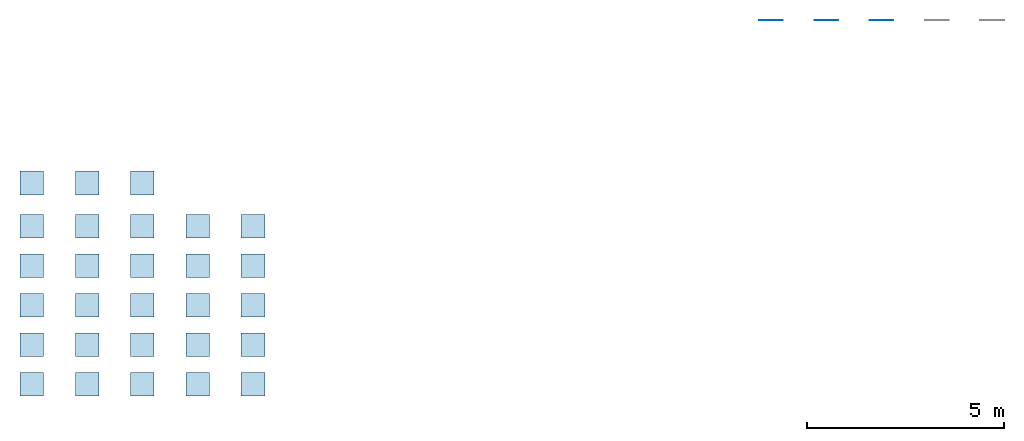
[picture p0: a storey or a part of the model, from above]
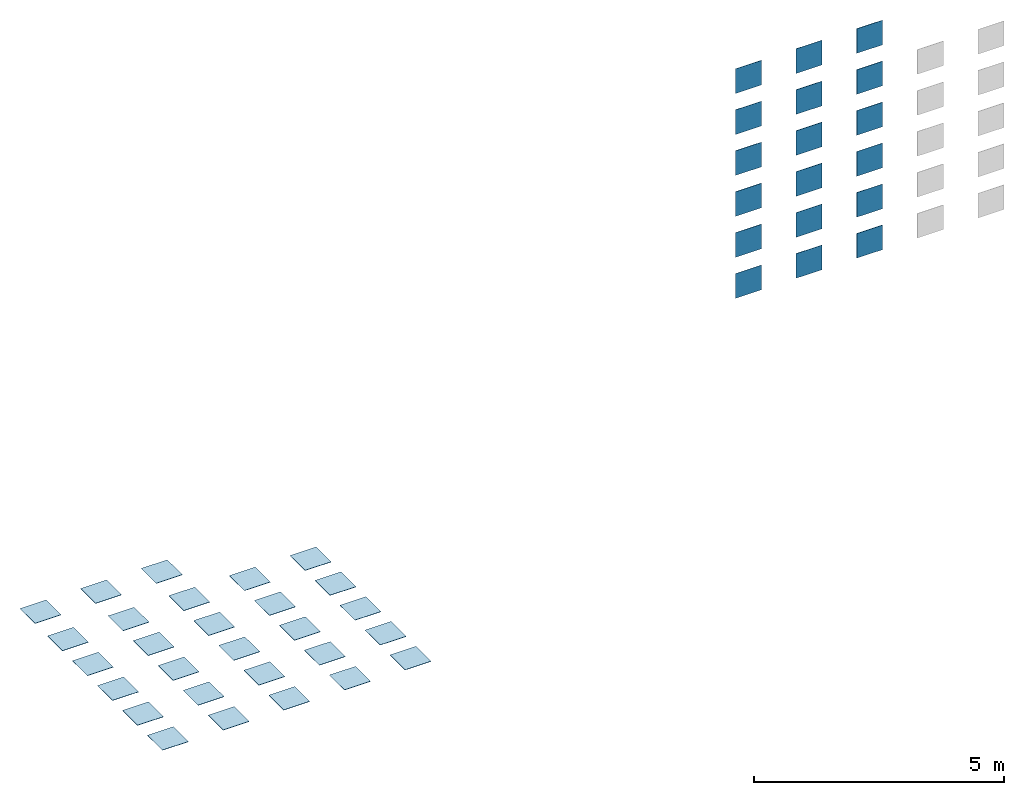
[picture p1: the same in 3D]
Properties of the parts of a building model (IFC2X3), part 1 of 2

# File
Description: ViewDefinition [CoordinationView]
File name: Número de proyecto
Time: 2017-10-18T16:32:32
Written by: The EXPRESS Data Manager Version 5.02.0100.07 : 28 Aug 2013
Made in: 20140606_1530(x64) - Exporter 2015.0.2014.0606 - Default UI
Comment: STEP Physical File produced by: The EXPRESS Data Manager Version 5.02.0100.07 : 28 Aug 2013 * Module: EDMstepFileFactory/EDMstandAlone * Creation date: Wed Oct 18 16:32:32 2017 * Host: REVIT * Database: C:\Users\corte\AppData\Local\Temp\{179764BC-A99F-427C-84EC-D29EAF626511}\ifc * Database version: 5507 * Database creation date: Wed Oct 18 16:32:31 2017 * Schema: IFC2X3 * Model: DataRepository.ifc * Model creation date: Wed Oct 18 16:32:31 2017 * Header model: DataRepository.ifc_HeaderModel * Header model creation date: Wed Oct 18 16:32:31 2017 * EDMuser: sdai-user * EDMgroup: sdai-group * License ID and type: 5605 : Permanent license. Expiry date: * EDMstepFileFactory options: 020000

# IfcProject, Número de proyecto
LongName: Nombre de proyecto; Phase: Estado de proyecto

# IfcSite, Default
RefLatitude: 40, 25, 0, 86975; RefLongitude: -3, -42, -1, -243858; RefElevation: 0 m
Otros - Categoría: Información de proyecto; Dirección de proyecto: Introduzca dirección aquí; Estado de proyecto: Estado de proyecto; Fecha de emisión de proyecto: Fecha de emisión; Nombre de cliente: Propietario; Nombre de proyecto: Nombre de proyecto; Número de proyecto: Número de proyecto

# IfcBuilding
Pset_BuildingCommon - NumberOfStoreys: 1
Otros - Categoría: Información de proyecto; Dirección de proyecto: Introduzca dirección aquí; Estado de proyecto: Estado de proyecto; Fecha de emisión de proyecto: Fecha de emisión; Nombre de cliente: Propietario; Nombre de proyecto: Nombre de proyecto; Número de proyecto: Número de proyecto

# IfcBuildingStorey, BENACO FLOOR TILES
LongName: BENACO FLOOR TILES; Elevation: 0 m
Restricciones - Altura base: Punto base del proyecto; Alzado: 0 m
Cotas - Altura de cálculo: 0 m
Datos de identidad - Estructura: no; Nombre: BENACO FLOOR TILES; Planta de edificio: yes; Nombre de tipo: Nivel 1
Otros - Categoría: Niveles; Familia: Nivel: Nivel 1; Familia y tipo: Nivel: Nivel 1; ID de tipo: Nivel: Nivel 1; Tipo: Nivel: Nivel 1; Nombre de familia: Nivel
Gráficos - Color: 0; Grosor de línea: 1; Patrón de línea: Trazo punto; Símbolo: Extremo de nivel: Extremo de nivel; Símbolo en extremo 1 por defecto: no; Símbolo en extremo 2 por defecto: yes

# IfcSlab: Suelo:VIVES BENACO BEIGE 20x20, Suelo:VIVES BENACO BEIGE 20x20:194564
In: BENACO FLOOR TILES
PredefinedType: FLOOR; Material: VIVES BENACO BEIGE 20x20 0.008 m
Pset_SlabCommon - IsExternal: no; LoadBearing: yes; PitchAngle: 0 deg; Reference: VIVES BENACO BEIGE 20x20; ThermalTransmittance: 187.5 kg/K/s3
Pset_ManufacturerTypeInformation - Manufacturer: VIVES Azulejos y Gres S.A.
Cotas - Área: 0.36 m2; Grosor: 0.008 m; Perímetro: 2.4 m; Volumen: 0.00288 m3
Estructura - Activar modelo analítico: no; Estructura: no
Otros - Categoría: Suelos; Familia: Suelo: VIVES BENACO BEIGE 20x20; Familia y tipo: Suelo: VIVES BENACO BEIGE 20x20; ID de tipo: Suelo: VIVES BENACO BEIGE 20x20; Tipo: Suelo: VIVES BENACO BEIGE 20x20; Nombre de familia: Suelo
Proceso por fases - Fase de creación: Nueva construcción
Restricciones - Delimitación de habitación: yes; Desfase de altura desde nivel: 0 m; Nivel: Nivel: BENACO FLOOR TILES; Relacionado con masa: no
Construcción - Función: Interior; Grosor predeterminado: 0.008 m
Datos - Model Name: BENACO BEIGE; Size: 20x20
Datos de identidad - Fabricante: VIVES Azulejos y Gres S.A.; Modelo: BENACO BEIGE 20x20; Nombre de tipo: VIVES BENACO BEIGE 20x20; URL: http://www.vivesceramica.com/bim/r/4Q47
Gráficos - Color de relleno de detalle bajo: 0
Propiedades analíticas - Aspereza: 3; Absortancia: 0.7; Coeficiente de transferencia de calor (U): 187.5; Masa térmica: 17285.6; Resistencia térmica (R): 0.00533333

# IfcSlab: Suelo:VIVES BENACO CORAL 20x20, Suelo:VIVES BENACO CORAL 20x20:194640
In: BENACO FLOOR TILES
PredefinedType: FLOOR; Material: VIVES BENACO CORAL 20x20 0.008 m
Pset_SlabCommon - IsExternal: no; LoadBearing: yes; PitchAngle: 0 deg; Reference: VIVES BENACO CORAL 20x20; ThermalTransmittance: 187.5 kg/K/s3
Pset_ManufacturerTypeInformation - Manufacturer: VIVES Azulejos y Gres S.A.
Cotas - Área: 0.36 m2; Grosor: 0.008 m; Perímetro: 2.4 m; Volumen: 0.00288 m3
Estructura - Activar modelo analítico: no; Estructura: no
Otros - Categoría: Suelos; Familia: Suelo: VIVES BENACO CORAL 20x20; Familia y tipo: Suelo: VIVES BENACO CORAL 20x20; ID de tipo: Suelo: VIVES BENACO CORAL 20x20; Tipo: Suelo: VIVES BENACO CORAL 20x20; Nombre de familia: Suelo
Proceso por fases - Fase de creación: Nueva construcción
Restricciones - Delimitación de habitación: yes; Desfase de altura desde nivel: 0 m; Relacionado con masa: no; Nivel: Nivel: BENACO FLOOR TILES
Construcción - Función: Interior; Grosor predeterminado: 0.008 m
Datos - Model Name: BENACO CORAL; Size: 20x20
Datos de identidad - Fabricante: VIVES Azulejos y Gres S.A.; Modelo: BENACO CORAL 20x20; Nombre de tipo: VIVES BENACO CORAL 20x20; URL: http://www.vivesceramica.com/bim/r/4Q48
Gráficos - Color de relleno de detalle bajo: 0
Propiedades analíticas - Aspereza: 3; Absortancia: 0.7; Coeficiente de transferencia de calor (U): 187.5; Masa térmica: 17285.6; Resistencia térmica (R): 0.00533333

# IfcSlab: Suelo:VIVES BENACO HUMO 20x20, Suelo:VIVES BENACO HUMO 20x20:194419
In: BENACO FLOOR TILES
PredefinedType: FLOOR; Material: VIVES BENACO HUMO 20x20 0.008 m
Pset_SlabCommon - IsExternal: no; LoadBearing: yes; PitchAngle: 0 deg; Reference: VIVES BENACO HUMO 20x20; ThermalTransmittance: 187.5 kg/K/s3
Pset_ManufacturerTypeInformation - Manufacturer: VIVES Azulejos y Gres S.A.
Cotas - Área: 0.36 m2; Grosor: 0.008 m; Perímetro: 2.4 m; Volumen: 0.00288 m3
Estructura - Activar modelo analítico: no; Estructura: no
Otros - Categoría: Suelos; Familia: Suelo: VIVES BENACO HUMO 20x20; Familia y tipo: Suelo: VIVES BENACO HUMO 20x20; ID de tipo: Suelo: VIVES BENACO HUMO 20x20; Tipo: Suelo: VIVES BENACO HUMO 20x20; Nombre de familia: Suelo
Proceso por fases - Fase de creación: Nueva construcción
Restricciones - Delimitación de habitación: yes; Desfase de altura desde nivel: 0 m; Relacionado con masa: no; Nivel: Nivel: BENACO FLOOR TILES
Construcción - Función: Interior; Grosor predeterminado: 0.008 m
Datos - Model Name: BENACO HUMO; Size: 20x20
Datos de identidad - Fabricante: VIVES Azulejos y Gres S.A.; Modelo: BENACO HUMO 20x20; Nombre de tipo: VIVES BENACO HUMO 20x20; URL: http://www.vivesceramica.com/bim/r/4Q45
Gráficos - Color de relleno de detalle bajo: 0
Propiedades analíticas - Aspereza: 3; Absortancia: 0.7; Coeficiente de transferencia de calor (U): 187.5; Masa térmica: 17285.6; Resistencia térmica (R): 0.00533333

# IfcSlab: Suelo:VIVES BENACO MAR 20x20, Suelo:VIVES BENACO MAR 20x20:194706
In: BENACO FLOOR TILES
PredefinedType: FLOOR; Material: VIVES BENACO MAR 20x20 0.008 m
Pset_SlabCommon - IsExternal: no; LoadBearing: yes; PitchAngle: 0 deg; Reference: VIVES BENACO MAR 20x20; ThermalTransmittance: 187.5 kg/K/s3
Pset_ManufacturerTypeInformation - Manufacturer: VIVES Azulejos y Gres S.A.
Cotas - Área: 0.36 m2; Grosor: 0.008 m; Perímetro: 2.4 m; Volumen: 0.00288 m3
Estructura - Activar modelo analítico: no; Estructura: no
Otros - Categoría: Suelos; Familia: Suelo: VIVES BENACO MAR 20x20; Familia y tipo: Suelo: VIVES BENACO MAR 20x20; ID de tipo: Suelo: VIVES BENACO MAR 20x20; Tipo: Suelo: VIVES BENACO MAR 20x20; Nombre de familia: Suelo
Proceso por fases - Fase de creación: Nueva construcción
Restricciones - Delimitación de habitación: yes; Desfase de altura desde nivel: 0 m; Relacionado con masa: no; Nivel: Nivel: BENACO FLOOR TILES
Construcción - Función: Interior; Grosor predeterminado: 0.008 m
Datos - Model Name: BENACO MAR; Size: 20x20
Datos de identidad - Fabricante: VIVES Azulejos y Gres S.A.; Modelo: BENACO MAR 20x20; Nombre de tipo: VIVES BENACO MAR 20x20; URL: http://www.vivesceramica.com/bim/r/4Q49
Gráficos - Color de relleno de detalle bajo: 0
Propiedades analíticas - Aspereza: 3; Absortancia: 0.7; Coeficiente de transferencia de calor (U): 187.5; Masa térmica: 17285.6; Resistencia térmica (R): 0.00533333

# IfcSlab: Suelo:VIVES BENACO NUBE 20x20, Suelo:VIVES BENACO NUBE 20x20:194483
In: BENACO FLOOR TILES
PredefinedType: FLOOR; Material: VIVES BENACO NUBE 20x20 0.008 m
Pset_SlabCommon - IsExternal: no; LoadBearing: yes; PitchAngle: 0 deg; Reference: VIVES BENACO NUBE 20x20; ThermalTransmittance: 187.5 kg/K/s3
Pset_ManufacturerTypeInformation - Manufacturer: VIVES Azulejos y Gres S.A.
Cotas - Área: 0.36 m2; Grosor: 0.008 m; Perímetro: 2.4 m; Volumen: 0.00288 m3
Estructura - Activar modelo analítico: no; Estructura: no
Otros - Categoría: Suelos; Familia: Suelo: VIVES BENACO NUBE 20x20; Familia y tipo: Suelo: VIVES BENACO NUBE 20x20; ID de tipo: Suelo: VIVES BENACO NUBE 20x20; Tipo: Suelo: VIVES BENACO NUBE 20x20; Nombre de familia: Suelo
Proceso por fases - Fase de creación: Nueva construcción
Restricciones - Delimitación de habitación: yes; Desfase de altura desde nivel: 0 m; Relacionado con masa: no; Nivel: Nivel: BENACO FLOOR TILES
Construcción - Función: Interior; Grosor predeterminado: 0.008 m
Datos - Model Name: BENACO NUBE; Size: 20x20
Datos de identidad - Fabricante: VIVES Azulejos y Gres S.A.; Modelo: BENACO NUBE 20x20; Nombre de tipo: VIVES BENACO NUBE 20x20; URL: http://www.vivesceramica.com/bim/r/4Q46
Gráficos - Color de relleno de detalle bajo: 0
Propiedades analíticas - Aspereza: 3; Absortancia: 0.7; Coeficiente de transferencia de calor (U): 187.5; Masa térmica: 17285.6; Resistencia térmica (R): 0.00533333

# IfcSlab: Suelo:VIVES CAROLE BEIGE 20x20, Suelo:VIVES CAROLE BEIGE 20x20:194801
In: BENACO FLOOR TILES
PredefinedType: FLOOR; Material: VIVES CAROLE BEIGE 20x20 0.008 m
Pset_SlabCommon - IsExternal: no; LoadBearing: yes; PitchAngle: 0 deg; Reference: VIVES CAROLE BEIGE 20x20; ThermalTransmittance: 187.5 kg/K/s3
Pset_ManufacturerTypeInformation - Manufacturer: VIVES Azulejos y Gres S.A.
Cotas - Área: 0.36 m2; Grosor: 0.008 m; Perímetro: 2.4 m; Volumen: 0.00288 m3
Estructura - Activar modelo analítico: no; Estructura: no
Otros - Categoría: Suelos; Familia: Suelo: VIVES CAROLE BEIGE 20x20; Familia y tipo: Suelo: VIVES CAROLE BEIGE 20x20; ID de tipo: Suelo: VIVES CAROLE BEIGE 20x20; Tipo: Suelo: VIVES CAROLE BEIGE 20x20; Nombre de familia: Suelo
Proceso por fases - Fase de creación: Nueva construcción
Restricciones - Delimitación de habitación: yes; Desfase de altura desde nivel: 0 m; Relacionado con masa: no; Nivel: Nivel: BENACO FLOOR TILES
Construcción - Función: Interior; Grosor predeterminado: 0.008 m
Datos - Model Name: CAROLE BEIGE; Size: 20x20
Datos de identidad - Fabricante: VIVES Azulejos y Gres S.A.; Modelo: CAROLE BEIGE 20x20; Nombre de tipo: VIVES CAROLE BEIGE 20x20; URL: http://www.vivesceramica.com/bim/r/4Q65
Gráficos - Color de relleno de detalle bajo: 0
Propiedades analíticas - Aspereza: 3; Absortancia: 0.7; Coeficiente de transferencia de calor (U): 187.5; Masa térmica: 17285.6; Resistencia térmica (R): 0.00533333

# IfcSlab: Suelo:VIVES CAROLE CORAL 20x20, Suelo:VIVES CAROLE CORAL 20x20:194809
In: BENACO FLOOR TILES
PredefinedType: FLOOR; Material: VIVES CAROLE CORAL 20x20 0.008 m
Pset_SlabCommon - IsExternal: no; LoadBearing: yes; PitchAngle: 0 deg; Reference: VIVES CAROLE CORAL 20x20; ThermalTransmittance: 187.5 kg/K/s3
Pset_ManufacturerTypeInformation - Manufacturer: VIVES Azulejos y Gres S.A.
Cotas - Área: 0.36 m2; Grosor: 0.008 m; Perímetro: 2.4 m; Volumen: 0.00288 m3
Estructura - Activar modelo analítico: no; Estructura: no
Otros - Categoría: Suelos; Familia: Suelo: VIVES CAROLE CORAL 20x20; Familia y tipo: Suelo: VIVES CAROLE CORAL 20x20; ID de tipo: Suelo: VIVES CAROLE CORAL 20x20; Tipo: Suelo: VIVES CAROLE CORAL 20x20; Nombre de familia: Suelo
Proceso por fases - Fase de creación: Nueva construcción
Restricciones - Delimitación de habitación: yes; Desfase de altura desde nivel: 0 m; Nivel: Nivel: BENACO FLOOR TILES; Relacionado con masa: no
Construcción - Función: Interior; Grosor predeterminado: 0.008 m
Datos - Model Name: CAROLE CORAL; Size: 20x20
Datos de identidad - Fabricante: VIVES Azulejos y Gres S.A.; Modelo: CAROLE CORAL 20x20; Nombre de tipo: VIVES CAROLE CORAL 20x20; URL: http://www.vivesceramica.com/bim/r/4Q66
Gráficos - Color de relleno de detalle bajo: 0
Propiedades analíticas - Aspereza: 3; Absortancia: 0.7; Coeficiente de transferencia de calor (U): 187.5; Masa térmica: 17285.6; Resistencia térmica (R): 0.00533333

# IfcSlab: Suelo:VIVES CAROLE HUMO 20x20, Suelo:VIVES CAROLE HUMO 20x20:194785
In: BENACO FLOOR TILES
PredefinedType: FLOOR; Material: VIVES CAROLE HUMO 20x20 0.008 m
Pset_SlabCommon - IsExternal: no; LoadBearing: yes; PitchAngle: 0 deg; Reference: VIVES CAROLE HUMO 20x20; ThermalTransmittance: 187.5 kg/K/s3
Pset_ManufacturerTypeInformation - Manufacturer: VIVES Azulejos y Gres S.A.
Cotas - Área: 0.36 m2; Grosor: 0.008 m; Perímetro: 2.4 m; Volumen: 0.00288 m3
Estructura - Activar modelo analítico: no; Estructura: no
Otros - Categoría: Suelos; Familia: Suelo: VIVES CAROLE HUMO 20x20; Familia y tipo: Suelo: VIVES CAROLE HUMO 20x20; ID de tipo: Suelo: VIVES CAROLE HUMO 20x20; Tipo: Suelo: VIVES CAROLE HUMO 20x20; Nombre de familia: Suelo
Proceso por fases - Fase de creación: Nueva construcción
Restricciones - Delimitación de habitación: yes; Desfase de altura desde nivel: 0 m; Nivel: Nivel: BENACO FLOOR TILES; Relacionado con masa: no
Construcción - Función: Interior; Grosor predeterminado: 0.008 m
Datos - Model Name: CAROLE HUMO; Size: 20x20
Datos de identidad - Fabricante: VIVES Azulejos y Gres S.A.; Modelo: CAROLE HUMO 20x20; Nombre de tipo: VIVES CAROLE HUMO 20x20; URL: http://www.vivesceramica.com/bim/r/4Q61
Gráficos - Color de relleno de detalle bajo: 0
Propiedades analíticas - Aspereza: 3; Absortancia: 0.7; Coeficiente de transferencia de calor (U): 187.5; Masa térmica: 17285.6; Resistencia térmica (R): 0.00533333

# IfcSlab: Suelo:VIVES CAROLE MAR 20x20, Suelo:VIVES CAROLE MAR 20x20:194817
In: BENACO FLOOR TILES
PredefinedType: FLOOR; Material: VIVES CAROLE MAR 20x20 0.008 m
Pset_SlabCommon - IsExternal: no; LoadBearing: yes; PitchAngle: 0 deg; Reference: VIVES CAROLE MAR 20x20; ThermalTransmittance: 187.5 kg/K/s3
Pset_ManufacturerTypeInformation - Manufacturer: VIVES Azulejos y Gres S.A.
Cotas - Área: 0.36 m2; Grosor: 0.008 m; Perímetro: 2.4 m; Volumen: 0.00288 m3
Estructura - Activar modelo analítico: no; Estructura: no
Otros - Categoría: Suelos; Familia: Suelo: VIVES CAROLE MAR 20x20; Familia y tipo: Suelo: VIVES CAROLE MAR 20x20; ID de tipo: Suelo: VIVES CAROLE MAR 20x20; Tipo: Suelo: VIVES CAROLE MAR 20x20; Nombre de familia: Suelo
Proceso por fases - Fase de creación: Nueva construcción
Restricciones - Delimitación de habitación: yes; Desfase de altura desde nivel: 0 m; Nivel: Nivel: BENACO FLOOR TILES; Relacionado con masa: no
Construcción - Función: Interior; Grosor predeterminado: 0.008 m
Datos - Model Name: CAROLE MAR; Size: 20x20
Datos de identidad - Fabricante: VIVES Azulejos y Gres S.A.; Modelo: CAROLE MAR 20x20; Nombre de tipo: VIVES CAROLE MAR 20x20; URL: http://www.vivesceramica.com/bim/r/4Q67
Gráficos - Color de relleno de detalle bajo: 0
Propiedades analíticas - Aspereza: 3; Absortancia: 0.7; Coeficiente de transferencia de calor (U): 187.5; Masa térmica: 17285.6; Resistencia térmica (R): 0.00533333

# IfcSlab: Suelo:VIVES CAROLE NUBE 20x20, Suelo:VIVES CAROLE NUBE 20x20:194793
In: BENACO FLOOR TILES
PredefinedType: FLOOR; Material: VIVES CAROLE NUBE 20x20 0.008 m
Pset_SlabCommon - IsExternal: no; LoadBearing: yes; PitchAngle: 0 deg; Reference: VIVES CAROLE NUBE 20x20; ThermalTransmittance: 187.5 kg/K/s3
Pset_ManufacturerTypeInformation - Manufacturer: VIVES Azulejos y Gres S.A.
Cotas - Área: 0.36 m2; Grosor: 0.008 m; Perímetro: 2.4 m; Volumen: 0.00288 m3
Estructura - Activar modelo analítico: no; Estructura: no
Otros - Categoría: Suelos; Familia: Suelo: VIVES CAROLE NUBE 20x20; Familia y tipo: Suelo: VIVES CAROLE NUBE 20x20; ID de tipo: Suelo: VIVES CAROLE NUBE 20x20; Tipo: Suelo: VIVES CAROLE NUBE 20x20; Nombre de familia: Suelo
Proceso por fases - Fase de creación: Nueva construcción
Restricciones - Delimitación de habitación: yes; Desfase de altura desde nivel: 0 m; Nivel: Nivel: BENACO FLOOR TILES; Relacionado con masa: no
Construcción - Función: Interior; Grosor predeterminado: 0.008 m
Datos - Model Name: CAROLE NUBE; Size: 20x20
Datos de identidad - Fabricante: VIVES Azulejos y Gres S.A.; Modelo: CAROLE NUBE 20x20; Nombre de tipo: VIVES CAROLE NUBE 20x20; URL: http://www.vivesceramica.com/bim/r/4Q64
Gráficos - Color de relleno de detalle bajo: 0
Propiedades analíticas - Aspereza: 3; Absortancia: 0.7; Coeficiente de transferencia de calor (U): 187.5; Masa térmica: 17285.6; Resistencia térmica (R): 0.00533333

# IfcSlab: Suelo:VIVES PIGNETO BEIGE 20x20, Suelo:VIVES PIGNETO BEIGE 20x20:195196
In: BENACO FLOOR TILES
PredefinedType: FLOOR; Material: VIVES PIGNETO BEIGE 20x20 0.008 m
Pset_SlabCommon - IsExternal: no; LoadBearing: yes; PitchAngle: 0 deg; Reference: VIVES PIGNETO BEIGE 20x20; ThermalTransmittance: 187.5 kg/K/s3
Pset_ManufacturerTypeInformation - Manufacturer: VIVES Azulejos y Gres S.A.
Cotas - Área: 0.36 m2; Grosor: 0.008 m; Perímetro: 2.4 m; Volumen: 0.00288 m3
Estructura - Activar modelo analítico: no; Estructura: no
Otros - Categoría: Suelos; Familia: Suelo: VIVES PIGNETO BEIGE 20x20; Familia y tipo: Suelo: VIVES PIGNETO BEIGE 20x20; ID de tipo: Suelo: VIVES PIGNETO BEIGE 20x20; Tipo: Suelo: VIVES PIGNETO BEIGE 20x20; Nombre de familia: Suelo
Proceso por fases - Fase de creación: Nueva construcción
Restricciones - Delimitación de habitación: yes; Desfase de altura desde nivel: 0 m; Relacionado con masa: no; Nivel: Nivel: BENACO FLOOR TILES
Construcción - Función: Interior; Grosor predeterminado: 0.008 m
Datos - Model Name: PIGNETO BEIGE; Size: 20x20
Datos de identidad - Fabricante: VIVES Azulejos y Gres S.A.; Modelo: PIGNETO BEIGE 20x20; Nombre de tipo: VIVES PIGNETO BEIGE 20x20; URL: http://www.vivesceramica.com/bim/r/4Q70
Gráficos - Color de relleno de detalle bajo: 0
Propiedades analíticas - Aspereza: 3; Absortancia: 0.7; Coeficiente de transferencia de calor (U): 187.5; Masa térmica: 17285.6; Resistencia térmica (R): 0.00533333

# IfcSlab: Suelo:VIVES PIGNETO CORAL 20x20, Suelo:VIVES PIGNETO CORAL 20x20:195204
In: BENACO FLOOR TILES
PredefinedType: FLOOR; Material: VIVES PIGNETO CORAL 20x20 0.008 m
Pset_SlabCommon - IsExternal: no; LoadBearing: yes; PitchAngle: 0 deg; Reference: VIVES PIGNETO CORAL 20x20; ThermalTransmittance: 187.5 kg/K/s3
Pset_ManufacturerTypeInformation - Manufacturer: VIVES Azulejos y Gres S.A.
Cotas - Área: 0.36 m2; Grosor: 0.008 m; Perímetro: 2.4 m; Volumen: 0.00288 m3
Estructura - Activar modelo analítico: no; Estructura: no
Otros - Categoría: Suelos; Familia: Suelo: VIVES PIGNETO CORAL 20x20; Familia y tipo: Suelo: VIVES PIGNETO CORAL 20x20; ID de tipo: Suelo: VIVES PIGNETO CORAL 20x20; Tipo: Suelo: VIVES PIGNETO CORAL 20x20; Nombre de familia: Suelo
Proceso por fases - Fase de creación: Nueva construcción
Restricciones - Delimitación de habitación: yes; Desfase de altura desde nivel: 0 m; Relacionado con masa: no; Nivel: Nivel: BENACO FLOOR TILES
Construcción - Función: Interior; Grosor predeterminado: 0.008 m
Datos - Model Name: PIGNETO CORAL; Size: 20x20
Datos de identidad - Fabricante: VIVES Azulejos y Gres S.A.; Modelo: PIGNETO CORAL 20x20; Nombre de tipo: VIVES PIGNETO CORAL 20x20; URL: http://www.vivesceramica.com/bim/r/4Q71
Gráficos - Color de relleno de detalle bajo: 0
Propiedades analíticas - Aspereza: 3; Absortancia: 0.7; Coeficiente de transferencia de calor (U): 187.5; Masa térmica: 17285.6; Resistencia térmica (R): 0.00533333

# IfcSlab: Suelo:VIVES PIGNETO HUMO 20x20, Suelo:VIVES PIGNETO HUMO 20x20:195180
In: BENACO FLOOR TILES
PredefinedType: FLOOR; Material: VIVES PIGNETO HUMO 20x20 0.008 m
Pset_SlabCommon - IsExternal: no; LoadBearing: yes; PitchAngle: 0 deg; Reference: VIVES PIGNETO HUMO 20x20; ThermalTransmittance: 187.5 kg/K/s3
Pset_ManufacturerTypeInformation - Manufacturer: VIVES Azulejos y Gres S.A.
Cotas - Área: 0.36 m2; Grosor: 0.008 m; Perímetro: 2.4 m; Volumen: 0.00288 m3
Estructura - Activar modelo analítico: no; Estructura: no
Otros - Categoría: Suelos; Familia: Suelo: VIVES PIGNETO HUMO 20x20; Familia y tipo: Suelo: VIVES PIGNETO HUMO 20x20; ID de tipo: Suelo: VIVES PIGNETO HUMO 20x20; Tipo: Suelo: VIVES PIGNETO HUMO 20x20; Nombre de familia: Suelo
Proceso por fases - Fase de creación: Nueva construcción
Restricciones - Delimitación de habitación: yes; Desfase de altura desde nivel: 0 m; Nivel: Nivel: BENACO FLOOR TILES; Relacionado con masa: no
Construcción - Función: Interior; Grosor predeterminado: 0.008 m
Datos - Model Name: PIGNETO HUMO; Size: 20x20
Datos de identidad - Fabricante: VIVES Azulejos y Gres S.A.; Modelo: PIGNETO HUMO 20x20; Nombre de tipo: VIVES PIGNETO HUMO 20x20; URL: http://www.vivesceramica.com/bim/r/4Q68
Gráficos - Color de relleno de detalle bajo: 0
Propiedades analíticas - Aspereza: 3; Absortancia: 0.7; Coeficiente de transferencia de calor (U): 187.5; Masa térmica: 17285.6; Resistencia térmica (R): 0.00533333

# IfcSlab: Suelo:VIVES PIGNETO MAR 20x20, Suelo:VIVES PIGNETO MAR 20x20:195212
In: BENACO FLOOR TILES
PredefinedType: FLOOR; Material: VIVES PIGNETO MAR 20x20 0.008 m
Pset_SlabCommon - IsExternal: no; LoadBearing: yes; PitchAngle: 0 deg; Reference: VIVES PIGNETO MAR 20x20; ThermalTransmittance: 187.5 kg/K/s3
Pset_ManufacturerTypeInformation - Manufacturer: VIVES Azulejos y Gres S.A.
Cotas - Área: 0.36 m2; Grosor: 0.008 m; Perímetro: 2.4 m; Volumen: 0.00288 m3
Estructura - Activar modelo analítico: no; Estructura: no
Otros - Categoría: Suelos; Familia: Suelo: VIVES PIGNETO MAR 20x20; Familia y tipo: Suelo: VIVES PIGNETO MAR 20x20; ID de tipo: Suelo: VIVES PIGNETO MAR 20x20; Tipo: Suelo: VIVES PIGNETO MAR 20x20; Nombre de familia: Suelo
Proceso por fases - Fase de creación: Nueva construcción
Restricciones - Delimitación de habitación: yes; Desfase de altura desde nivel: 0 m; Relacionado con masa: no; Nivel: Nivel: BENACO FLOOR TILES
Construcción - Función: Interior; Grosor predeterminado: 0.008 m
Datos - Model Name: PIGNETO MAR; Size: 20x20
Datos de identidad - Fabricante: VIVES Azulejos y Gres S.A.; Modelo: PIGNETO MAR 20x20; Nombre de tipo: VIVES PIGNETO MAR 20x20; URL: http://www.vivesceramica.com/bim/r/4Q72
Gráficos - Color de relleno de detalle bajo: 0
Propiedades analíticas - Aspereza: 3; Absortancia: 0.7; Coeficiente de transferencia de calor (U): 187.5; Masa térmica: 17285.6; Resistencia térmica (R): 0.00533333

# IfcSlab: Suelo:VIVES PIGNETO NUBE 20x20, Suelo:VIVES PIGNETO NUBE 20x20:195188
In: BENACO FLOOR TILES
PredefinedType: FLOOR; Material: VIVES PIGNETO NUBE 20x20 0.008 m
Pset_SlabCommon - IsExternal: no; LoadBearing: yes; PitchAngle: 0 deg; Reference: VIVES PIGNETO NUBE 20x20; ThermalTransmittance: 187.5 kg/K/s3
Pset_ManufacturerTypeInformation - Manufacturer: VIVES Azulejos y Gres S.A.
Cotas - Área: 0.36 m2; Grosor: 0.008 m; Perímetro: 2.4 m; Volumen: 0.00288 m3
Estructura - Activar modelo analítico: no; Estructura: no
Otros - Categoría: Suelos; Familia: Suelo: VIVES PIGNETO NUBE 20x20; Familia y tipo: Suelo: VIVES PIGNETO NUBE 20x20; ID de tipo: Suelo: VIVES PIGNETO NUBE 20x20; Tipo: Suelo: VIVES PIGNETO NUBE 20x20; Nombre de familia: Suelo
Proceso por fases - Fase de creación: Nueva construcción
Restricciones - Delimitación de habitación: yes; Desfase de altura desde nivel: 0 m; Relacionado con masa: no; Nivel: Nivel: BENACO FLOOR TILES
Construcción - Función: Interior; Grosor predeterminado: 0.008 m
Datos - Model Name: PIGNETO NUBE; Size: 20x20
Datos de identidad - Fabricante: VIVES Azulejos y Gres S.A.; Modelo: PIGNETO NUBE 20x20; Nombre de tipo: VIVES PIGNETO NUBE 20x20; URL: http://www.vivesceramica.com/bim/r/4Q69
Gráficos - Color de relleno de detalle bajo: 0
Propiedades analíticas - Aspereza: 3; Absortancia: 0.7; Coeficiente de transferencia de calor (U): 187.5; Masa térmica: 17285.6; Resistencia térmica (R): 0.00533333

# IfcSlab: Suelo:VIVES TERCELLO BEIGE 20x20, Suelo:VIVES TERCELLO BEIGE 20x20:195589
In: BENACO FLOOR TILES
PredefinedType: FLOOR; Material: VIVES TERCELLO BEIGE 20x20 0.008 m
Pset_SlabCommon - IsExternal: no; LoadBearing: yes; PitchAngle: 0 deg; Reference: VIVES TERCELLO BEIGE 20x20; ThermalTransmittance: 187.5 kg/K/s3
Pset_ManufacturerTypeInformation - Manufacturer: VIVES Azulejos y Gres S.A.
Cotas - Área: 0.36 m2; Grosor: 0.008 m; Perímetro: 2.4 m; Volumen: 0.00288 m3
Estructura - Activar modelo analítico: no; Estructura: no
Otros - Categoría: Suelos; Familia: Suelo: VIVES TERCELLO BEIGE 20x20; Familia y tipo: Suelo: VIVES TERCELLO BEIGE 20x20; ID de tipo: Suelo: VIVES TERCELLO BEIGE 20x20; Tipo: Suelo: VIVES TERCELLO BEIGE 20x20; Nombre de familia: Suelo
Proceso por fases - Fase de creación: Nueva construcción
Restricciones - Delimitación de habitación: yes; Desfase de altura desde nivel: 0 m; Relacionado con masa: no; Nivel: Nivel: BENACO FLOOR TILES
Construcción - Función: Interior; Grosor predeterminado: 0.008 m
Datos - Model Name: TERCELLO BEIGE; Size: 20x20
Datos de identidad - Fabricante: VIVES Azulejos y Gres S.A.; Modelo: TERCELLO BEIGE 20x20; Nombre de tipo: VIVES TERCELLO BEIGE 20x20; URL: http://www.vivesceramica.com/bim/r/4Q75
Gráficos - Color de relleno de detalle bajo: 0
Propiedades analíticas - Aspereza: 3; Absortancia: 0.7; Coeficiente de transferencia de calor (U): 187.5; Masa térmica: 17285.6; Resistencia térmica (R): 0.00533333

# IfcSlab: Suelo:VIVES TERCELLO CORAL 20x20, Suelo:VIVES TERCELLO CORAL 20x20:195597
In: BENACO FLOOR TILES
PredefinedType: FLOOR; Material: VIVES TERCELLO CORAL 20x20 0.008 m
Pset_SlabCommon - IsExternal: no; LoadBearing: yes; PitchAngle: 0 deg; Reference: VIVES TERCELLO CORAL 20x20; ThermalTransmittance: 187.5 kg/K/s3
Pset_ManufacturerTypeInformation - Manufacturer: VIVES Azulejos y Gres S.A.
Cotas - Área: 0.36 m2; Grosor: 0.008 m; Perímetro: 2.4 m; Volumen: 0.00288 m3
Estructura - Activar modelo analítico: no; Estructura: no
Otros - Categoría: Suelos; Familia: Suelo: VIVES TERCELLO CORAL 20x20; Familia y tipo: Suelo: VIVES TERCELLO CORAL 20x20; ID de tipo: Suelo: VIVES TERCELLO CORAL 20x20; Tipo: Suelo: VIVES TERCELLO CORAL 20x20; Nombre de familia: Suelo
Proceso por fases - Fase de creación: Nueva construcción
Restricciones - Delimitación de habitación: yes; Desfase de altura desde nivel: 0 m; Nivel: Nivel: BENACO FLOOR TILES; Relacionado con masa: no
Construcción - Función: Interior; Grosor predeterminado: 0.008 m
Datos - Model Name: TERCELLO CORAL; Size: 20x20
Datos de identidad - Fabricante: VIVES Azulejos y Gres S.A.; Modelo: TERCELLO CORAL 20x20; Nombre de tipo: VIVES TERCELLO CORAL 20x20; URL: http://www.vivesceramica.com/bim/r/4Q76
Gráficos - Color de relleno de detalle bajo: 0
Propiedades analíticas - Aspereza: 3; Absortancia: 0.7; Coeficiente de transferencia de calor (U): 187.5; Masa térmica: 17285.6; Resistencia térmica (R): 0.00533333

# IfcSlab: Suelo:VIVES TERCELLO HUMO 20x20, Suelo:VIVES TERCELLO HUMO 20x20:195573
In: BENACO FLOOR TILES
PredefinedType: FLOOR; Material: VIVES TERCELLO HUMO 20x20 0.008 m
Pset_SlabCommon - IsExternal: no; LoadBearing: yes; PitchAngle: 0 deg; Reference: VIVES TERCELLO HUMO 20x20; ThermalTransmittance: 187.5 kg/K/s3
Pset_ManufacturerTypeInformation - Manufacturer: VIVES Azulejos y Gres S.A.
Cotas - Área: 0.36 m2; Grosor: 0.008 m; Perímetro: 2.4 m; Volumen: 0.00288 m3
Estructura - Activar modelo analítico: no; Estructura: no
Otros - Categoría: Suelos; Familia: Suelo: VIVES TERCELLO HUMO 20x20; Familia y tipo: Suelo: VIVES TERCELLO HUMO 20x20; ID de tipo: Suelo: VIVES TERCELLO HUMO 20x20; Tipo: Suelo: VIVES TERCELLO HUMO 20x20; Nombre de familia: Suelo
Proceso por fases - Fase de creación: Nueva construcción
Restricciones - Delimitación de habitación: yes; Desfase de altura desde nivel: 0 m; Relacionado con masa: no; Nivel: Nivel: BENACO FLOOR TILES
Construcción - Función: Interior; Grosor predeterminado: 0.008 m
Datos - Model Name: TERCELLO HUMO; Size: 20x20
Datos de identidad - Fabricante: VIVES Azulejos y Gres S.A.; Modelo: TERCELLO HUMO 20x20; Nombre de tipo: VIVES TERCELLO HUMO 20x20; URL: http://www.vivesceramica.com/bim/r/4Q73
Gráficos - Color de relleno de detalle bajo: 0
Propiedades analíticas - Aspereza: 3; Absortancia: 0.7; Coeficiente de transferencia de calor (U): 187.5; Masa térmica: 17285.6; Resistencia térmica (R): 0.00533333

# IfcSlab: Suelo:VIVES TERCELLO MAR 20x20, Suelo:VIVES TERCELLO MAR 20x20:195605
In: BENACO FLOOR TILES
PredefinedType: FLOOR; Material: VIVES TERCELLO MAR 20x20 0.008 m
Pset_SlabCommon - IsExternal: no; LoadBearing: yes; PitchAngle: 0 deg; Reference: VIVES TERCELLO MAR 20x20; ThermalTransmittance: 187.5 kg/K/s3
Pset_ManufacturerTypeInformation - Manufacturer: VIVES Azulejos y Gres S.A.
Cotas - Área: 0.36 m2; Grosor: 0.008 m; Perímetro: 2.4 m; Volumen: 0.00288 m3
Estructura - Activar modelo analítico: no; Estructura: no
Otros - Categoría: Suelos; Familia: Suelo: VIVES TERCELLO MAR 20x20; Familia y tipo: Suelo: VIVES TERCELLO MAR 20x20; ID de tipo: Suelo: VIVES TERCELLO MAR 20x20; Tipo: Suelo: VIVES TERCELLO MAR 20x20; Nombre de familia: Suelo
Proceso por fases - Fase de creación: Nueva construcción
Restricciones - Delimitación de habitación: yes; Desfase de altura desde nivel: 0 m; Nivel: Nivel: BENACO FLOOR TILES; Relacionado con masa: no
Construcción - Función: Interior; Grosor predeterminado: 0.008 m
Datos - Model Name: TERCELLO MAR; Size: 20x20
Datos de identidad - Fabricante: VIVES Azulejos y Gres S.A.; Modelo: TERCELLO MAR 20x20; Nombre de tipo: VIVES TERCELLO MAR 20x20; URL: http://www.vivesceramica.com/bim/r/4Q77
Gráficos - Color de relleno de detalle bajo: 0
Propiedades analíticas - Aspereza: 3; Absortancia: 0.7; Coeficiente de transferencia de calor (U): 187.5; Masa térmica: 17285.6; Resistencia térmica (R): 0.00533333

# IfcSlab: Suelo:VIVES TERCELLO NUBE 20x20, Suelo:VIVES TERCELLO NUBE 20x20:195581
In: BENACO FLOOR TILES
PredefinedType: FLOOR; Material: VIVES TERCELLO NUBE 20x20 0.008 m
Pset_SlabCommon - IsExternal: no; LoadBearing: yes; PitchAngle: 0 deg; Reference: VIVES TERCELLO NUBE 20x20; ThermalTransmittance: 187.5 kg/K/s3
Pset_ManufacturerTypeInformation - Manufacturer: VIVES Azulejos y Gres S.A.
Cotas - Área: 0.36 m2; Grosor: 0.008 m; Perímetro: 2.4 m; Volumen: 0.00288 m3
Estructura - Activar modelo analítico: no; Estructura: no
Otros - Categoría: Suelos; Familia: Suelo: VIVES TERCELLO NUBE 20x20; Familia y tipo: Suelo: VIVES TERCELLO NUBE 20x20; ID de tipo: Suelo: VIVES TERCELLO NUBE 20x20; Tipo: Suelo: VIVES TERCELLO NUBE 20x20; Nombre de familia: Suelo
Proceso por fases - Fase de creación: Nueva construcción
Restricciones - Delimitación de habitación: yes; Desfase de altura desde nivel: 0 m; Nivel: Nivel: BENACO FLOOR TILES; Relacionado con masa: no
Construcción - Función: Interior; Grosor predeterminado: 0.008 m
Datos - Model Name: TERCELLO NUBE; Size: 20x20
Datos de identidad - Fabricante: VIVES Azulejos y Gres S.A.; Modelo: TERCELLO NUBE 20x20; Nombre de tipo: VIVES TERCELLO NUBE 20x20; URL: http://www.vivesceramica.com/bim/r/4Q74
Gráficos - Color de relleno de detalle bajo: 0
Propiedades analíticas - Aspereza: 3; Absortancia: 0.7; Coeficiente de transferencia de calor (U): 187.5; Masa térmica: 17285.6; Resistencia térmica (R): 0.00533333

# IfcSlab: Suelo:VIVES VODEVIL ANTRACITA 20x20, Suelo:VIVES VODEVIL ANTRACITA 20x20:193724
In: BENACO FLOOR TILES
PredefinedType: FLOOR; Material: VIVES VODEVIL ANTRACITA 20x20 0.008 m
Pset_SlabCommon - IsExternal: no; LoadBearing: yes; PitchAngle: 0 deg; Reference: VIVES VODEVIL ANTRACITA 20x20; ThermalTransmittance: 187.5 kg/K/s3
Pset_ManufacturerTypeInformation - Manufacturer: VIVES Azulejos y Gres S.A.
Cotas - Área: 0.36 m2; Grosor: 0.008 m; Perímetro: 2.4 m; Volumen: 0.00288 m3
Estructura - Activar modelo analítico: no; Estructura: no
Otros - Categoría: Suelos; Familia: Suelo: VIVES VODEVIL ANTRACITA 20x20; Familia y tipo: Suelo: VIVES VODEVIL ANTRACITA 20x20; ID de tipo: Suelo: VIVES VODEVIL ANTRACITA 20x20; Tipo: Suelo: VIVES VODEVIL ANTRACITA 20x20; Nombre de familia: Suelo
Proceso por fases - Fase de creación: Nueva construcción
Restricciones - Delimitación de habitación: yes; Desfase de altura desde nivel: 0 m; Nivel: Nivel: BENACO FLOOR TILES; Relacionado con masa: no
Construcción - Función: Interior; Grosor predeterminado: 0.008 m
Datos - Model Name: VODEVIL ANTRACITA; Size: 20x20
Datos de identidad - Fabricante: VIVES Azulejos y Gres S.A.; Modelo: VODEVIL ANTRACITA 20x20; Nombre de tipo: VIVES VODEVIL ANTRACITA 20x20; URL: http://www.vivesceramica.com/bim/r/4P12
Gráficos - Color de relleno de detalle bajo: 0
Propiedades analíticas - Aspereza: 3; Absortancia: 0.7; Coeficiente de transferencia de calor (U): 187.5; Masa térmica: 17285.6; Resistencia térmica (R): 0.00533333

# IfcSlab: Suelo:VIVES VODEVIL BEIGE 20x20, Suelo:VIVES VODEVIL BEIGE 20x20:194092
In: BENACO FLOOR TILES
PredefinedType: FLOOR; Material: VIVES VODEVIL BEIGE 20x20 0.008 m
Pset_SlabCommon - IsExternal: no; LoadBearing: yes; PitchAngle: 0 deg; Reference: VIVES VODEVIL BEIGE 20x20; ThermalTransmittance: 187.5 kg/K/s3
Pset_ManufacturerTypeInformation - Manufacturer: VIVES Azulejos y Gres S.A.
Cotas - Área: 0.36 m2; Grosor: 0.008 m; Perímetro: 2.4 m; Volumen: 0.00288 m3
Estructura - Activar modelo analítico: no; Estructura: no
Otros - Categoría: Suelos; Familia: Suelo: VIVES VODEVIL BEIGE 20x20; Familia y tipo: Suelo: VIVES VODEVIL BEIGE 20x20; ID de tipo: Suelo: VIVES VODEVIL BEIGE 20x20; Tipo: Suelo: VIVES VODEVIL BEIGE 20x20; Nombre de familia: Suelo
Proceso por fases - Fase de creación: Nueva construcción
Restricciones - Delimitación de habitación: yes; Desfase de altura desde nivel: 0 m; Relacionado con masa: no; Nivel: Nivel: BENACO FLOOR TILES
Construcción - Función: Interior; Grosor predeterminado: 0.008 m
Datos - Model Name: VODEVIL BEIGE; Size: 20x20
Datos de identidad - Fabricante: VIVES Azulejos y Gres S.A.; Modelo: VODEVIL BEIGE 20x20; Nombre de tipo: VIVES VODEVIL BEIGE 20x20; URL: http://www.vivesceramica.com/bim/r/4P13
Gráficos - Color de relleno de detalle bajo: 0
Propiedades analíticas - Aspereza: 3; Absortancia: 0.7; Coeficiente de transferencia de calor (U): 187.5; Masa térmica: 17285.6; Resistencia térmica (R): 0.00533333

# IfcSlab: Suelo:VIVES VODEVIL CORAL 20x20, Suelo:VIVES VODEVIL CORAL 20x20:194201
In: BENACO FLOOR TILES
PredefinedType: FLOOR; Material: VIVES VODEVIL CORAL 20x20 0.008 m
Pset_SlabCommon - IsExternal: no; LoadBearing: yes; PitchAngle: 0 deg; Reference: VIVES VODEVIL CORAL 20x20; ThermalTransmittance: 187.5 kg/K/s3
Pset_ManufacturerTypeInformation - Manufacturer: VIVES Azulejos y Gres S.A.
Cotas - Área: 0.36 m2; Grosor: 0.008 m; Perímetro: 2.4 m; Volumen: 0.00288 m3
Estructura - Activar modelo analítico: no; Estructura: no
Otros - Categoría: Suelos; Familia: Suelo: VIVES VODEVIL CORAL 20x20; Familia y tipo: Suelo: VIVES VODEVIL CORAL 20x20; ID de tipo: Suelo: VIVES VODEVIL CORAL 20x20; Tipo: Suelo: VIVES VODEVIL CORAL 20x20; Nombre de familia: Suelo
Proceso por fases - Fase de creación: Nueva construcción
Restricciones - Delimitación de habitación: yes; Desfase de altura desde nivel: 0 m; Relacionado con masa: no; Nivel: Nivel: BENACO FLOOR TILES
Construcción - Función: Interior; Grosor predeterminado: 0.008 m
Datos - Model Name: VODEVIL CORAL; Size: 20x20
Datos de identidad - Fabricante: VIVES Azulejos y Gres S.A.; Modelo: VODEVIL CORAL 20x20; Nombre de tipo: VIVES VODEVIL CORAL 20x20; URL: http://www.vivesceramica.com/bim/r/4Q78
Gráficos - Color de relleno de detalle bajo: 0
Propiedades analíticas - Aspereza: 3; Absortancia: 0.7; Coeficiente de transferencia de calor (U): 187.5; Masa térmica: 17285.6; Resistencia térmica (R): 0.00533333

# IfcSlab: Suelo:VIVES VODEVIL HUMO 20x20, Suelo:VIVES VODEVIL HUMO 20x20:193858
In: BENACO FLOOR TILES
PredefinedType: FLOOR; Material: VIVES VODEVIL HUMO 20x20 0.008 m
Pset_SlabCommon - IsExternal: no; LoadBearing: yes; PitchAngle: 0 deg; Reference: VIVES VODEVIL HUMO 20x20; ThermalTransmittance: 187.5 kg/K/s3
Pset_ManufacturerTypeInformation - Manufacturer: VIVES Azulejos y Gres S.A.
Cotas - Área: 0.36 m2; Grosor: 0.008 m; Perímetro: 2.4 m; Volumen: 0.00288 m3
Estructura - Activar modelo analítico: no; Estructura: no
Otros - Categoría: Suelos; Familia: Suelo: VIVES VODEVIL HUMO 20x20; Familia y tipo: Suelo: VIVES VODEVIL HUMO 20x20; ID de tipo: Suelo: VIVES VODEVIL HUMO 20x20; Tipo: Suelo: VIVES VODEVIL HUMO 20x20; Nombre de familia: Suelo
Proceso por fases - Fase de creación: Nueva construcción
Restricciones - Delimitación de habitación: yes; Desfase de altura desde nivel: 0 m; Nivel: Nivel: BENACO FLOOR TILES; Relacionado con masa: no
Construcción - Función: Interior; Grosor predeterminado: 0.008 m
Datos - Model Name: VODEVIL HUMO; Size: 20x20
Datos de identidad - Fabricante: VIVES Azulejos y Gres S.A.; Modelo: VODEVIL HUMO 20x20; Nombre de tipo: VIVES VODEVIL HUMO 20x20; URL: http://www.vivesceramica.com/bim/r/4Q45
Gráficos - Color de relleno de detalle bajo: 0
Propiedades analíticas - Aspereza: 3; Absortancia: 0.7; Coeficiente de transferencia de calor (U): 187.5; Masa térmica: 17285.6; Resistencia térmica (R): 0.00533333

# IfcSlab: Suelo:VIVES VODEVIL MAR 20x20, Suelo:VIVES VODEVIL MAR 20x20:194340
In: BENACO FLOOR TILES
PredefinedType: FLOOR; Material: VIVES VODEVIL MAR 20x20 0.008 m
Pset_SlabCommon - IsExternal: no; LoadBearing: yes; PitchAngle: 0 deg; Reference: VIVES VODEVIL MAR 20x20; ThermalTransmittance: 187.5 kg/K/s3
Pset_ManufacturerTypeInformation - Manufacturer: VIVES Azulejos y Gres S.A.
Cotas - Área: 0.36 m2; Grosor: 0.008 m; Perímetro: 2.4 m; Volumen: 0.00288 m3
Estructura - Activar modelo analítico: no; Estructura: no
Otros - Categoría: Suelos; Familia: Suelo: VIVES VODEVIL MAR 20x20; Familia y tipo: Suelo: VIVES VODEVIL MAR 20x20; ID de tipo: Suelo: VIVES VODEVIL MAR 20x20; Tipo: Suelo: VIVES VODEVIL MAR 20x20; Nombre de familia: Suelo
Proceso por fases - Fase de creación: Nueva construcción
Restricciones - Delimitación de habitación: yes; Desfase de altura desde nivel: 0 m; Relacionado con masa: no; Nivel: Nivel: BENACO FLOOR TILES
Construcción - Función: Interior; Grosor predeterminado: 0.008 m
Datos - Model Name: VODEVIL MAR; Size: 20x20
Datos de identidad - Fabricante: VIVES Azulejos y Gres S.A.; Modelo: VODEVIL MAR 20x20; Nombre de tipo: VIVES VODEVIL MAR 20x20; URL: http://www.vivesceramica.com/bim/r/4Q79
Gráficos - Color de relleno de detalle bajo: 0
Propiedades analíticas - Aspereza: 3; Absortancia: 0.7; Coeficiente de transferencia de calor (U): 187.5; Masa térmica: 17285.6; Resistencia térmica (R): 0.00533333

# IfcSlab: Suelo:VIVES VODEVIL MARRON 20x20, Suelo:VIVES VODEVIL MARRON 20x20:193773
In: BENACO FLOOR TILES
PredefinedType: FLOOR; Material: VIVES VODEVIL MARRON 20x20 0.008 m
Pset_SlabCommon - IsExternal: no; LoadBearing: yes; PitchAngle: 0 deg; Reference: VIVES VODEVIL MARRON 20x20; ThermalTransmittance: 187.5 kg/K/s3
Pset_ManufacturerTypeInformation - Manufacturer: VIVES Azulejos y Gres S.A.
Cotas - Área: 0.36 m2; Grosor: 0.008 m; Perímetro: 2.4 m; Volumen: 0.00288 m3
Estructura - Activar modelo analítico: no; Estructura: no
Otros - Categoría: Suelos; Familia: Suelo: VIVES VODEVIL MARRON 20x20; Familia y tipo: Suelo: VIVES VODEVIL MARRON 20x20; ID de tipo: Suelo: VIVES VODEVIL MARRON 20x20; Tipo: Suelo: VIVES VODEVIL MARRON 20x20; Nombre de familia: Suelo
Proceso por fases - Fase de creación: Nueva construcción
Restricciones - Delimitación de habitación: yes; Desfase de altura desde nivel: 0 m; Relacionado con masa: no; Nivel: Nivel: BENACO FLOOR TILES
Construcción - Función: Interior; Grosor predeterminado: 0.008 m
Datos - Model Name: VODEVIL MARRON; Size: 20x20
Datos de identidad - Fabricante: VIVES Azulejos y Gres S.A.; Modelo: VODEVIL MARRON 20x20; Nombre de tipo: VIVES VODEVIL MARRON 20x20; URL: http://www.vivesceramica.com/bim/r/4P15
Gráficos - Color de relleno de detalle bajo: 0
Propiedades analíticas - Aspereza: 3; Absortancia: 0.7; Coeficiente de transferencia de calor (U): 187.5; Masa térmica: 17285.6; Resistencia térmica (R): 0.00533333

# IfcSlab: Suelo:VIVES VODEVIL NACAR 20x20, Suelo:VIVES VODEVIL NACAR 20x20:189750
In: BENACO FLOOR TILES
PredefinedType: FLOOR; Material: VIVES VODEVIL NACAR 20x20 0.008 m
Pset_SlabCommon - Reference: VIVES VODEVIL NACAR 20x20; IsExternal: no; LoadBearing: yes; ThermalTransmittance: 187.5 kg/K/s3; PitchAngle: 0 deg
Pset_ManufacturerTypeInformation - Manufacturer: VIVES Azulejos y Gres S.A.
Cotas - Área: 0.36 m2; Grosor: 0.008 m; Perímetro: 2.4 m; Volumen: 0.00288 m3
Estructura - Activar modelo analítico: no; Estructura: no
Otros - Categoría: Suelos; Familia: Suelo: VIVES VODEVIL NACAR 20x20; Familia y tipo: Suelo: VIVES VODEVIL NACAR 20x20; ID de tipo: Suelo: VIVES VODEVIL NACAR 20x20; Tipo: Suelo: VIVES VODEVIL NACAR 20x20; Nombre de familia: Suelo
Proceso por fases - Fase de creación: Nueva construcción
Restricciones - Delimitación de habitación: yes; Desfase de altura desde nivel: 0 m; Nivel: Nivel: BENACO FLOOR TILES; Relacionado con masa: no
Construcción - Función: Interior; Grosor predeterminado: 0.008 m
Datos - Model Name: VODEVIL NACAR; Size: 20x20
Datos de identidad - Fabricante: VIVES Azulejos y Gres S.A.; Modelo: VODEVIL NACAR 20x20; Nombre de tipo: VIVES VODEVIL NACAR 20x20; URL: http://www.vivesceramica.com/bim/r/4P16
Gráficos - Color de relleno de detalle bajo: 0
Propiedades analíticas - Absortancia: 0.7; Aspereza: 3; Coeficiente de transferencia de calor (U): 187.5; Masa térmica: 17285.6; Resistencia térmica (R): 0.00533333

# IfcSlab: Suelo:VIVES VODEVIL NUBE 20x20, Suelo:VIVES VODEVIL NUBE 20x20:193923
In: BENACO FLOOR TILES
PredefinedType: FLOOR; Material: VIVES VODEVIL NUBE 20x20 0.008 m
Pset_SlabCommon - IsExternal: no; LoadBearing: yes; PitchAngle: 0 deg; Reference: VIVES VODEVIL NUBE 20x20; ThermalTransmittance: 187.5 kg/K/s3
Pset_ManufacturerTypeInformation - Manufacturer: VIVES Azulejos y Gres S.A.
Cotas - Área: 0.36 m2; Grosor: 0.008 m; Perímetro: 2.4 m; Volumen: 0.00288 m3
Estructura - Activar modelo analítico: no; Estructura: no
Otros - Categoría: Suelos; Familia: Suelo: VIVES VODEVIL NUBE 20x20; Familia y tipo: Suelo: VIVES VODEVIL NUBE 20x20; ID de tipo: Suelo: VIVES VODEVIL NUBE 20x20; Tipo: Suelo: VIVES VODEVIL NUBE 20x20; Nombre de familia: Suelo
Proceso por fases - Fase de creación: Nueva construcción
Restricciones - Delimitación de habitación: yes; Desfase de altura desde nivel: 0 m; Nivel: Nivel: BENACO FLOOR TILES; Relacionado con masa: no
Construcción - Función: Interior; Grosor predeterminado: 0.008 m
Datos - Model Name: VODEVIL NUBE; Size: 20x20
Datos de identidad - Fabricante: VIVES Azulejos y Gres S.A.; Modelo: VODEVIL NUBE 20x20; Nombre de tipo: VIVES VODEVIL NUBE 20x20; URL: http://www.vivesceramica.com/bim/r/4P17
Gráficos - Color de relleno de detalle bajo: 0
Propiedades analíticas - Aspereza: 3; Absortancia: 0.7; Coeficiente de transferencia de calor (U): 187.5; Masa térmica: 17285.6; Resistencia térmica (R): 0.00533333

# IfcWallStandardCase: Muro básico:VIVES BENACO BEIGE 20x20, Muro básico:VIVES BENACO BEIGE 20x20:196754
In: BENACO FLOOR TILES
Type - PredefinedType: STANDARD; Material: VIVES BENACO BEIGE 20x20 0.008 m
Type - Construcción - Función: Interior; Envolvente en extremos: Ninguno; Envolvente en inserciones: Sin envolvente; Anchura: 0.008 m
Type - Datos - Model Name: BENACO BEIGE; Size: 20x20
Type - Datos de identidad - Fabricante: VIVES Azulejos y Gres S.A.; Modelo: BENACO BEIGE 20x20; Nombre de tipo: VIVES BENACO BEIGE 20x20; URL: http://www.vivesceramica.com/bim/r/4Q47
Type - Gráficos - Color de relleno de detalle bajo: 0
Type - Otros - Categoría: Muros; Nombre de familia: Muro básico
Type - Propiedades analíticas - Aspereza: 3; Absortancia: 0.7; Coeficiente de transferencia de calor (U): 187.5; Masa térmica: 17285.6; Resistencia térmica (R): 0.00533333
Cotas - Área: 0.36 m2; Longitud: 0.6 m; Volumen: 0.00288 m3
Estructura - Activar modelo analítico: no; Estructura: no; Uso estructural: No portante
Otros - Familia: Muro básico: VIVES BENACO BEIGE 20x20; Familia y tipo: Muro básico: VIVES BENACO BEIGE 20x20; ID de tipo: Muro básico: VIVES BENACO BEIGE 20x20; Tipo: Muro básico: VIVES BENACO BEIGE 20x20
Proceso por fases - Fase de creación: Nueva construcción
Restricciones - Delimitación de habitación: yes; Relacionado con masa: no; Desfase superior: 0 m; Distancia de extensión de base: 0 m; Distancia de extensión superior: 0 m; La base está enlazada: no; La parte superior está enlazada: no; Línea de ubicación: Cara de núcleo: Exterior; Restricción de base: Nivel: BENACO FLOOR TILES; Altura desconectada: 0.6 m; Desfase de base: 1.7 m
Pset_WallCommon - IsExternal: no; LoadBearing: no; ExtendToStructure: no; Reference: VIVES BENACO BEIGE 20x20; ThermalTransmittance: 187.5 kg/K/s3
Pset_ManufacturerTypeInformation - Manufacturer: VIVES Azulejos y Gres S.A.

# IfcWallStandardCase: Muro básico:VIVES BENACO CORAL 20x20, Muro básico:VIVES BENACO CORAL 20x20:196770
In: BENACO FLOOR TILES
Type - PredefinedType: STANDARD; Material: VIVES BENACO CORAL 20x20 0.008 m
Type - Construcción - Función: Interior; Envolvente en extremos: Ninguno; Envolvente en inserciones: Sin envolvente; Anchura: 0.008 m
Type - Datos - Model Name: BENACO CORAL; Size: 20x20
Type - Datos de identidad - Fabricante: VIVES Azulejos y Gres S.A.; Modelo: BENACO CORAL 20x20; Nombre de tipo: VIVES BENACO CORAL 20x20; URL: http://www.vivesceramica.com/bim/r/4Q48
Type - Gráficos - Color de relleno de detalle bajo: 0
Type - Otros - Categoría: Muros; Nombre de familia: Muro básico
Type - Propiedades analíticas - Aspereza: 3; Absortancia: 0.7; Coeficiente de transferencia de calor (U): 187.5; Masa térmica: 17285.6; Resistencia térmica (R): 0.00533333
Cotas - Área: 0.36 m2; Longitud: 0.6 m; Volumen: 0.00288 m3
Estructura - Activar modelo analítico: no; Estructura: no; Uso estructural: No portante
Otros - Familia: Muro básico: VIVES BENACO CORAL 20x20; Familia y tipo: Muro básico: VIVES BENACO CORAL 20x20; ID de tipo: Muro básico: VIVES BENACO CORAL 20x20; Tipo: Muro básico: VIVES BENACO CORAL 20x20
Proceso por fases - Fase de creación: Nueva construcción
Restricciones - Delimitación de habitación: yes; Relacionado con masa: no; Desfase superior: 0 m; Distancia de extensión de base: 0 m; Distancia de extensión superior: 0 m; La base está enlazada: no; La parte superior está enlazada: no; Línea de ubicación: Cara de núcleo: Exterior; Restricción de base: Nivel: BENACO FLOOR TILES; Altura desconectada: 0.6 m; Desfase de base: 1.7 m
Pset_WallCommon - IsExternal: no; LoadBearing: no; ExtendToStructure: no; Reference: VIVES BENACO CORAL 20x20; ThermalTransmittance: 187.5 kg/K/s3
Pset_ManufacturerTypeInformation - Manufacturer: VIVES Azulejos y Gres S.A.

# IfcWallStandardCase: Muro básico:VIVES BENACO HUMO 20x20, Muro básico:VIVES BENACO HUMO 20x20:196722
In: BENACO FLOOR TILES
Type - PredefinedType: STANDARD; Material: VIVES BENACO HUMO 20x20 0.008 m
Type - Construcción - Función: Interior; Envolvente en extremos: Ninguno; Envolvente en inserciones: Sin envolvente; Anchura: 0.008 m
Type - Datos - Model Name: BENACO HUMO; Size: 20x20
Type - Datos de identidad - Fabricante: VIVES Azulejos y Gres S.A.; Modelo: BENACO HUMO 20x20; Nombre de tipo: VIVES BENACO HUMO 20x20; URL: http://www.vivesceramica.com/bim/r/4Q45
Type - Gráficos - Color de relleno de detalle bajo: 0
Type - Otros - Categoría: Muros; Nombre de familia: Muro básico
Type - Propiedades analíticas - Aspereza: 3; Absortancia: 0.7; Coeficiente de transferencia de calor (U): 187.5; Masa térmica: 17285.6; Resistencia térmica (R): 0.00533333
Cotas - Área: 0.36 m2; Longitud: 0.6 m; Volumen: 0.00288 m3
Estructura - Activar modelo analítico: no; Estructura: no; Uso estructural: No portante
Otros - Familia: Muro básico: VIVES BENACO HUMO 20x20; Familia y tipo: Muro básico: VIVES BENACO HUMO 20x20; ID de tipo: Muro básico: VIVES BENACO HUMO 20x20; Tipo: Muro básico: VIVES BENACO HUMO 20x20
Proceso por fases - Fase de creación: Nueva construcción
Restricciones - Delimitación de habitación: yes; Relacionado con masa: no; Desfase superior: 0 m; Distancia de extensión de base: 0 m; Distancia de extensión superior: 0 m; La base está enlazada: no; La parte superior está enlazada: no; Línea de ubicación: Cara de núcleo: Exterior; Restricción de base: Nivel: BENACO FLOOR TILES; Altura desconectada: 0.6 m; Desfase de base: 1.7 m
Pset_WallCommon - IsExternal: no; LoadBearing: no; ExtendToStructure: no; Reference: VIVES BENACO HUMO 20x20; ThermalTransmittance: 187.5 kg/K/s3
Pset_ManufacturerTypeInformation - Manufacturer: VIVES Azulejos y Gres S.A.

# IfcWallStandardCase: Muro básico:VIVES BENACO MAR 20x20, Muro básico:VIVES BENACO MAR 20x20:196786
In: BENACO FLOOR TILES
Type - PredefinedType: STANDARD; Material: VIVES BENACO MAR 20x20 0.008 m
Type - Construcción - Función: Interior; Envolvente en extremos: Ninguno; Envolvente en inserciones: Sin envolvente; Anchura: 0.008 m
Type - Datos - Model Name: BENACO MAR; Size: 20x20
Type - Datos de identidad - Fabricante: VIVES Azulejos y Gres S.A.; Modelo: BENACO MAR 20x20; Nombre de tipo: VIVES BENACO MAR 20x20; URL: http://www.vivesceramica.com/bim/r/4Q49
Type - Gráficos - Color de relleno de detalle bajo: 0
Type - Otros - Categoría: Muros; Nombre de familia: Muro básico
Type - Propiedades analíticas - Aspereza: 3; Absortancia: 0.7; Coeficiente de transferencia de calor (U): 187.5; Masa térmica: 17285.6; Resistencia térmica (R): 0.00533333
Cotas - Área: 0.36 m2; Longitud: 0.6 m; Volumen: 0.00288 m3
Estructura - Activar modelo analítico: no; Estructura: no; Uso estructural: No portante
Otros - Familia: Muro básico: VIVES BENACO MAR 20x20; Familia y tipo: Muro básico: VIVES BENACO MAR 20x20; ID de tipo: Muro básico: VIVES BENACO MAR 20x20; Tipo: Muro básico: VIVES BENACO MAR 20x20
Proceso por fases - Fase de creación: Nueva construcción
Restricciones - Delimitación de habitación: yes; Relacionado con masa: no; Desfase superior: 0 m; Distancia de extensión de base: 0 m; Distancia de extensión superior: 0 m; La base está enlazada: no; La parte superior está enlazada: no; Línea de ubicación: Cara de núcleo: Exterior; Restricción de base: Nivel: BENACO FLOOR TILES; Altura desconectada: 0.6 m; Desfase de base: 1.7 m
Pset_WallCommon - IsExternal: no; LoadBearing: no; ExtendToStructure: no; Reference: VIVES BENACO MAR 20x20; ThermalTransmittance: 187.5 kg/K/s3
Pset_ManufacturerTypeInformation - Manufacturer: VIVES Azulejos y Gres S.A.

# IfcWallStandardCase: Muro básico:VIVES BENACO NUBE 20x20, Muro básico:VIVES BENACO NUBE 20x20:196738
In: BENACO FLOOR TILES
Type - PredefinedType: STANDARD; Material: VIVES BENACO NUBE 20x20 0.008 m
Type - Construcción - Función: Interior; Envolvente en extremos: Ninguno; Envolvente en inserciones: Sin envolvente; Anchura: 0.008 m
Type - Datos - Model Name: BENACO NUBE; Size: 20x20
Type - Datos de identidad - Fabricante: VIVES Azulejos y Gres S.A.; Modelo: BENACO NUBE 20x20; Nombre de tipo: VIVES BENACO NUBE 20x20; URL: http://www.vivesceramica.com/bim/r/4Q46
Type - Gráficos - Color de relleno de detalle bajo: 0
Type - Otros - Categoría: Muros; Nombre de familia: Muro básico
Type - Propiedades analíticas - Aspereza: 3; Absortancia: 0.7; Coeficiente de transferencia de calor (U): 187.5; Masa térmica: 17285.6; Resistencia térmica (R): 0.00533333
Cotas - Área: 0.36 m2; Longitud: 0.6 m; Volumen: 0.00288 m3
Estructura - Activar modelo analítico: no; Estructura: no; Uso estructural: No portante
Otros - Familia: Muro básico: VIVES BENACO NUBE 20x20; Familia y tipo: Muro básico: VIVES BENACO NUBE 20x20; ID de tipo: Muro básico: VIVES BENACO NUBE 20x20; Tipo: Muro básico: VIVES BENACO NUBE 20x20
Proceso por fases - Fase de creación: Nueva construcción
Restricciones - Delimitación de habitación: yes; Relacionado con masa: no; Desfase superior: 0 m; Distancia de extensión de base: 0 m; Distancia de extensión superior: 0 m; La base está enlazada: no; La parte superior está enlazada: no; Línea de ubicación: Cara de núcleo: Exterior; Restricción de base: Nivel: BENACO FLOOR TILES; Altura desconectada: 0.6 m; Desfase de base: 1.7 m
Pset_WallCommon - IsExternal: no; LoadBearing: no; ExtendToStructure: no; Reference: VIVES BENACO NUBE 20x20; ThermalTransmittance: 187.5 kg/K/s3
Pset_ManufacturerTypeInformation - Manufacturer: VIVES Azulejos y Gres S.A.

# IfcWallStandardCase: Muro básico:VIVES CAROLE BEIGE 20x20, Muro básico:VIVES CAROLE BEIGE 20x20:197599
In: BENACO FLOOR TILES
Type - PredefinedType: STANDARD; Material: VIVES CAROLE BEIGE 20x20 0.008 m
Type - Construcción - Función: Interior; Envolvente en extremos: Ninguno; Envolvente en inserciones: Sin envolvente; Anchura: 0.008 m
Type - Datos - Model Name: CAROLE BEIGE; Size: 20x20
Type - Datos de identidad - Fabricante: VIVES Azulejos y Gres S.A.; Modelo: CAROLE BEIGE 20x20; Nombre de tipo: VIVES CAROLE BEIGE 20x20; URL: http://www.vivesceramica.com/bim/r/4Q65
Type - Gráficos - Color de relleno de detalle bajo: 0
Type - Otros - Categoría: Muros; Nombre de familia: Muro básico
Type - Propiedades analíticas - Aspereza: 3; Absortancia: 0.7; Coeficiente de transferencia de calor (U): 187.5; Masa térmica: 17285.6; Resistencia térmica (R): 0.00533333
Cotas - Área: 0.36 m2; Longitud: 0.6 m; Volumen: 0.00288 m3
Estructura - Activar modelo analítico: no; Estructura: no; Uso estructural: No portante
Otros - Familia: Muro básico: VIVES CAROLE BEIGE 20x20; Familia y tipo: Muro básico: VIVES CAROLE BEIGE 20x20; ID de tipo: Muro básico: VIVES CAROLE BEIGE 20x20; Tipo: Muro básico: VIVES CAROLE BEIGE 20x20
Proceso por fases - Fase de creación: Nueva construcción
Restricciones - Delimitación de habitación: yes; Relacionado con masa: no; Desfase superior: 0 m; Distancia de extensión de base: 0 m; Distancia de extensión superior: 0 m; La base está enlazada: no; La parte superior está enlazada: no; Línea de ubicación: Cara de núcleo: Exterior; Restricción de base: Nivel: BENACO FLOOR TILES; Altura desconectada: 0.6 m; Desfase de base: 0.7 m
Pset_WallCommon - IsExternal: no; LoadBearing: no; ExtendToStructure: no; Reference: VIVES CAROLE BEIGE 20x20; ThermalTransmittance: 187.5 kg/K/s3
Pset_ManufacturerTypeInformation - Manufacturer: VIVES Azulejos y Gres S.A.

# IfcWallStandardCase: Muro básico:VIVES CAROLE CORAL 20x20, Muro básico:VIVES CAROLE CORAL 20x20:197615
In: BENACO FLOOR TILES
Type - PredefinedType: STANDARD; Material: VIVES CAROLE CORAL 20x20 0.008 m
Type - Construcción - Función: Interior; Envolvente en extremos: Ninguno; Envolvente en inserciones: Sin envolvente; Anchura: 0.008 m
Type - Datos - Model Name: CAROLE CORAL; Size: 20x20
Type - Datos de identidad - Fabricante: VIVES Azulejos y Gres S.A.; Modelo: CAROLE CORAL 20x20; Nombre de tipo: VIVES CAROLE CORAL 20x20; URL: http://www.vivesceramica.com/bim/r/4Q66
Type - Gráficos - Color de relleno de detalle bajo: 0
Type - Otros - Categoría: Muros; Nombre de familia: Muro básico
Type - Propiedades analíticas - Aspereza: 3; Absortancia: 0.7; Coeficiente de transferencia de calor (U): 187.5; Masa térmica: 17285.6; Resistencia térmica (R): 0.00533333
Cotas - Área: 0.36 m2; Longitud: 0.6 m; Volumen: 0.00288 m3
Estructura - Activar modelo analítico: no; Estructura: no; Uso estructural: No portante
Otros - Familia: Muro básico: VIVES CAROLE CORAL 20x20; Familia y tipo: Muro básico: VIVES CAROLE CORAL 20x20; ID de tipo: Muro básico: VIVES CAROLE CORAL 20x20; Tipo: Muro básico: VIVES CAROLE CORAL 20x20
Proceso por fases - Fase de creación: Nueva construcción
Restricciones - Delimitación de habitación: yes; Relacionado con masa: no; Desfase superior: 0 m; Distancia de extensión de base: 0 m; Distancia de extensión superior: 0 m; La base está enlazada: no; La parte superior está enlazada: no; Línea de ubicación: Cara de núcleo: Exterior; Restricción de base: Nivel: BENACO FLOOR TILES; Altura desconectada: 0.6 m; Desfase de base: 0.7 m
Pset_WallCommon - IsExternal: no; LoadBearing: no; ExtendToStructure: no; Reference: VIVES CAROLE CORAL 20x20; ThermalTransmittance: 187.5 kg/K/s3
Pset_ManufacturerTypeInformation - Manufacturer: VIVES Azulejos y Gres S.A.

# IfcWallStandardCase: Muro básico:VIVES CAROLE HUMO 20x20, Muro básico:VIVES CAROLE HUMO 20x20:197567
In: BENACO FLOOR TILES
Type - PredefinedType: STANDARD; Material: VIVES CAROLE HUMO 20x20 0.008 m
Type - Construcción - Función: Interior; Envolvente en extremos: Ninguno; Envolvente en inserciones: Sin envolvente; Anchura: 0.008 m
Type - Datos - Model Name: CAROLE HUMO; Size: 20x20
Type - Datos de identidad - Fabricante: VIVES Azulejos y Gres S.A.; Modelo: CAROLE HUMO 20x20; Nombre de tipo: VIVES CAROLE HUMO 20x20; URL: http://www.vivesceramica.com/bim/r/4Q61
Type - Gráficos - Color de relleno de detalle bajo: 0
Type - Otros - Categoría: Muros; Nombre de familia: Muro básico
Type - Propiedades analíticas - Aspereza: 3; Absortancia: 0.7; Coeficiente de transferencia de calor (U): 187.5; Masa térmica: 17285.6; Resistencia térmica (R): 0.00533333
Cotas - Área: 0.36 m2; Longitud: 0.6 m; Volumen: 0.00288 m3
Estructura - Activar modelo analítico: no; Estructura: no; Uso estructural: No portante
Otros - Familia: Muro básico: VIVES CAROLE HUMO 20x20; Familia y tipo: Muro básico: VIVES CAROLE HUMO 20x20; ID de tipo: Muro básico: VIVES CAROLE HUMO 20x20; Tipo: Muro básico: VIVES CAROLE HUMO 20x20
Proceso por fases - Fase de creación: Nueva construcción
Restricciones - Delimitación de habitación: yes; Relacionado con masa: no; Desfase superior: 0 m; Distancia de extensión de base: 0 m; Distancia de extensión superior: 0 m; La base está enlazada: no; La parte superior está enlazada: no; Línea de ubicación: Cara de núcleo: Exterior; Restricción de base: Nivel: BENACO FLOOR TILES; Altura desconectada: 0.6 m; Desfase de base: 0.7 m
Pset_WallCommon - IsExternal: no; LoadBearing: no; ExtendToStructure: no; Reference: VIVES CAROLE HUMO 20x20; ThermalTransmittance: 187.5 kg/K/s3
Pset_ManufacturerTypeInformation - Manufacturer: VIVES Azulejos y Gres S.A.

# IfcWallStandardCase: Muro básico:VIVES CAROLE MAR 20x20 2, Muro básico:VIVES CAROLE MAR 20x20 2:197631
In: BENACO FLOOR TILES
Type - PredefinedType: STANDARD; Material: VIVES CAROLE MAR 20x20 0.008 m
Type - Construcción - Función: Interior; Envolvente en extremos: Ninguno; Envolvente en inserciones: Sin envolvente; Anchura: 0.008 m
Type - Datos - Model Name: CAROLE MAR; Size: 20x20
Type - Datos de identidad - Fabricante: VIVES Azulejos y Gres S.A.; Modelo: CAROLE MAR 20x20; Nombre de tipo: VIVES CAROLE MAR 20x20 2; URL: http://www.vivesceramica.com/bim/r/4Q67
Type - Gráficos - Color de relleno de detalle bajo: 0
Type - Otros - Categoría: Muros; Nombre de familia: Muro básico
Type - Propiedades analíticas - Aspereza: 3; Absortancia: 0.7; Coeficiente de transferencia de calor (U): 187.5; Masa térmica: 17285.6; Resistencia térmica (R): 0.00533333
Cotas - Área: 0.36 m2; Longitud: 0.6 m; Volumen: 0.00288 m3
Estructura - Activar modelo analítico: no; Estructura: no; Uso estructural: No portante
Otros - Familia: Muro básico: VIVES CAROLE MAR 20x20 2; Familia y tipo: Muro básico: VIVES CAROLE MAR 20x20 2; ID de tipo: Muro básico: VIVES CAROLE MAR 20x20 2; Tipo: Muro básico: VIVES CAROLE MAR 20x20 2
Proceso por fases - Fase de creación: Nueva construcción
Restricciones - Delimitación de habitación: yes; Relacionado con masa: no; Desfase superior: 0 m; Distancia de extensión de base: 0 m; Distancia de extensión superior: 0 m; La base está enlazada: no; La parte superior está enlazada: no; Línea de ubicación: Cara de núcleo: Exterior; Restricción de base: Nivel: BENACO FLOOR TILES; Altura desconectada: 0.6 m; Desfase de base: 0.7 m
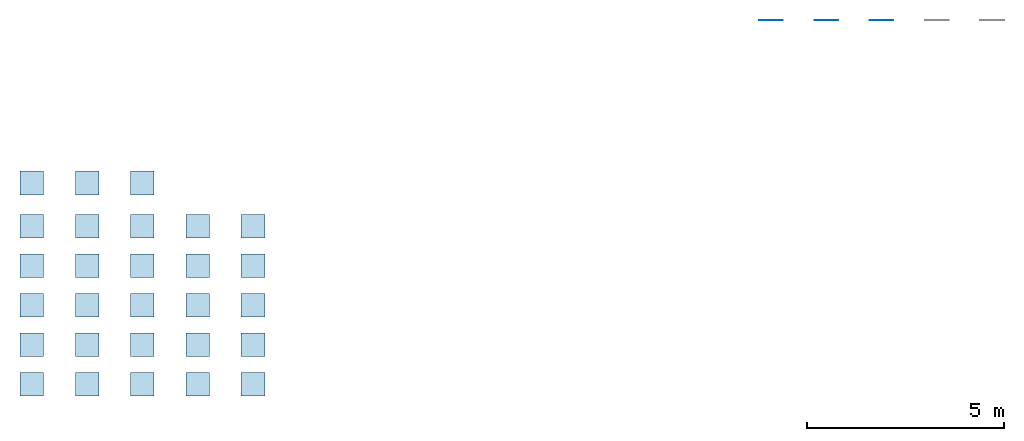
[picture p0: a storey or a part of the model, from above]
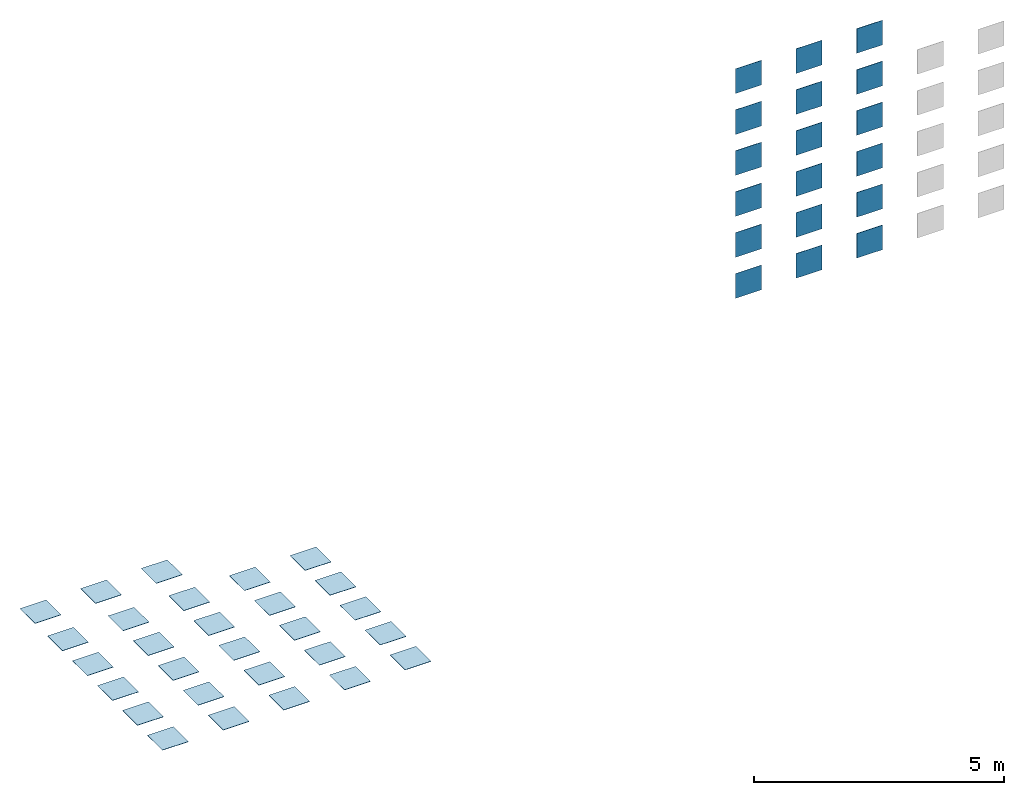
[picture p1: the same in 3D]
Properties of the parts of a building model (IFC2X3), part 2 of 2

# IfcWallStandardCase: Muro básico:VIVES CAROLE MAR 20x20 2, Muro básico:VIVES CAROLE MAR 20x20 2:197631
Pset_WallCommon - IsExternal: no; LoadBearing: no; ExtendToStructure: no; Reference: VIVES CAROLE MAR 20x20 2; ThermalTransmittance: 187.5 kg/K/s3
Pset_ManufacturerTypeInformation - Manufacturer: VIVES Azulejos y Gres S.A.

# IfcWallStandardCase: Muro básico:VIVES CAROLE NUBE 20x20, Muro básico:VIVES CAROLE NUBE 20x20:197583
In: BENACO FLOOR TILES
Type - PredefinedType: STANDARD; Material: VIVES CAROLE NUBE 20x20 0.008 m
Type - Construcción - Función: Interior; Envolvente en extremos: Ninguno; Envolvente en inserciones: Sin envolvente; Anchura: 0.008 m
Type - Datos - Model Name: CAROLE NUBE; Size: 20x20
Type - Datos de identidad - Fabricante: VIVES Azulejos y Gres S.A.; Modelo: CAROLE NUBE 20x20; Nombre de tipo: VIVES CAROLE NUBE 20x20; URL: http://www.vivesceramica.com/bim/r/4Q64
Type - Gráficos - Color de relleno de detalle bajo: 0
Type - Otros - Categoría: Muros; Nombre de familia: Muro básico
Type - Propiedades analíticas - Aspereza: 3; Absortancia: 0.7; Coeficiente de transferencia de calor (U): 187.5; Masa térmica: 17285.6; Resistencia térmica (R): 0.00533333
Cotas - Área: 0.36 m2; Longitud: 0.6 m; Volumen: 0.00288 m3
Estructura - Activar modelo analítico: no; Estructura: no; Uso estructural: No portante
Otros - Familia: Muro básico: VIVES CAROLE NUBE 20x20; Familia y tipo: Muro básico: VIVES CAROLE NUBE 20x20; ID de tipo: Muro básico: VIVES CAROLE NUBE 20x20; Tipo: Muro básico: VIVES CAROLE NUBE 20x20
Proceso por fases - Fase de creación: Nueva construcción
Restricciones - Delimitación de habitación: yes; Relacionado con masa: no; Desfase superior: 0 m; Distancia de extensión de base: 0 m; Distancia de extensión superior: 0 m; La base está enlazada: no; La parte superior está enlazada: no; Línea de ubicación: Cara de núcleo: Exterior; Restricción de base: Nivel: BENACO FLOOR TILES; Altura desconectada: 0.6 m; Desfase de base: 0.7 m
Pset_WallCommon - IsExternal: no; LoadBearing: no; ExtendToStructure: no; Reference: VIVES CAROLE NUBE 20x20; ThermalTransmittance: 187.5 kg/K/s3
Pset_ManufacturerTypeInformation - Manufacturer: VIVES Azulejos y Gres S.A.

# IfcWallStandardCase: Muro básico:VIVES PIGNETO BEIGE 20x20, Muro básico:VIVES PIGNETO BEIGE 20x20:198194
In: BENACO FLOOR TILES
Type - PredefinedType: STANDARD; Material: VIVES PIGNETO BEIGE 20x20 0.008 m
Type - Construcción - Función: Interior; Envolvente en extremos: Ninguno; Envolvente en inserciones: Sin envolvente; Anchura: 0.008 m
Type - Datos - Model Name: PIGNETO BEIGE; Size: 20x20
Type - Datos de identidad - Fabricante: VIVES Azulejos y Gres S.A.; Modelo: PIGNETO BEIGE 20x20; Nombre de tipo: VIVES PIGNETO BEIGE 20x20; URL: http://www.vivesceramica.com/bim/r/4Q70
Type - Gráficos - Color de relleno de detalle bajo: 0
Type - Otros - Categoría: Muros; Nombre de familia: Muro básico
Type - Propiedades analíticas - Aspereza: 3; Absortancia: 0.7; Coeficiente de transferencia de calor (U): 187.5; Masa térmica: 17285.6; Resistencia térmica (R): 0.00533333
Cotas - Área: 0.36 m2; Longitud: 0.6 m; Volumen: 0.00288 m3
Estructura - Activar modelo analítico: no; Estructura: no; Uso estructural: No portante
Otros - Familia: Muro básico: VIVES PIGNETO BEIGE 20x20; Familia y tipo: Muro básico: VIVES PIGNETO BEIGE 20x20; ID de tipo: Muro básico: VIVES PIGNETO BEIGE 20x20; Tipo: Muro básico: VIVES PIGNETO BEIGE 20x20
Proceso por fases - Fase de creación: Nueva construcción
Restricciones - Delimitación de habitación: yes; Relacionado con masa: no; Desfase superior: 0 m; Distancia de extensión de base: 0 m; Distancia de extensión superior: 0 m; La base está enlazada: no; La parte superior está enlazada: no; Línea de ubicación: Cara de núcleo: Exterior; Restricción de base: Nivel: BENACO FLOOR TILES; Altura desconectada: 0.6 m; Desfase de base: -0.3 m
Pset_WallCommon - IsExternal: no; LoadBearing: no; ExtendToStructure: no; Reference: VIVES PIGNETO BEIGE 20x20; ThermalTransmittance: 187.5 kg/K/s3
Pset_ManufacturerTypeInformation - Manufacturer: VIVES Azulejos y Gres S.A.

# IfcWallStandardCase: Muro básico:VIVES PIGNETO CORAL 20x20, Muro básico:VIVES PIGNETO CORAL 20x20:198210
In: BENACO FLOOR TILES
Type - PredefinedType: STANDARD; Material: VIVES PIGNETO CORAL 20x20 0.008 m
Type - Construcción - Función: Interior; Envolvente en extremos: Ninguno; Envolvente en inserciones: Sin envolvente; Anchura: 0.008 m
Type - Datos - Model Name: PIGNETO CORAL; Size: 20x20
Type - Datos de identidad - Fabricante: VIVES Azulejos y Gres S.A.; Modelo: PIGNETO CORAL 20x20; Nombre de tipo: VIVES PIGNETO CORAL 20x20; URL: http://www.vivesceramica.com/bim/r/4Q71
Type - Gráficos - Color de relleno de detalle bajo: 0
Type - Otros - Categoría: Muros; Nombre de familia: Muro básico
Type - Propiedades analíticas - Aspereza: 3; Absortancia: 0.7; Coeficiente de transferencia de calor (U): 187.5; Masa térmica: 17285.6; Resistencia térmica (R): 0.00533333
Cotas - Área: 0.36 m2; Longitud: 0.6 m; Volumen: 0.00288 m3
Estructura - Activar modelo analítico: no; Estructura: no; Uso estructural: No portante
Otros - Familia: Muro básico: VIVES PIGNETO CORAL 20x20; Familia y tipo: Muro básico: VIVES PIGNETO CORAL 20x20; ID de tipo: Muro básico: VIVES PIGNETO CORAL 20x20; Tipo: Muro básico: VIVES PIGNETO CORAL 20x20
Proceso por fases - Fase de creación: Nueva construcción
Restricciones - Delimitación de habitación: yes; Relacionado con masa: no; Desfase superior: 0 m; Distancia de extensión de base: 0 m; Distancia de extensión superior: 0 m; La base está enlazada: no; La parte superior está enlazada: no; Línea de ubicación: Cara de núcleo: Exterior; Restricción de base: Nivel: BENACO FLOOR TILES; Altura desconectada: 0.6 m; Desfase de base: -0.3 m
Pset_WallCommon - IsExternal: no; LoadBearing: no; ExtendToStructure: no; Reference: VIVES PIGNETO CORAL 20x20; ThermalTransmittance: 187.5 kg/K/s3
Pset_ManufacturerTypeInformation - Manufacturer: VIVES Azulejos y Gres S.A.

# IfcWallStandardCase: Muro básico:VIVES PIGNETO HUMO 20x20, Muro básico:VIVES PIGNETO HUMO 20x20:198162
In: BENACO FLOOR TILES
Type - PredefinedType: STANDARD; Material: VIVES PIGNETO HUMO 20x20 0.008 m
Type - Construcción - Función: Interior; Envolvente en extremos: Ninguno; Envolvente en inserciones: Sin envolvente; Anchura: 0.008 m
Type - Datos - Model Name: PIGNETO HUMO; Size: 20x20
Type - Datos de identidad - Fabricante: VIVES Azulejos y Gres S.A.; Modelo: PIGNETO HUMO 20x20; Nombre de tipo: VIVES PIGNETO HUMO 20x20; URL: http://www.vivesceramica.com/bim/r/4Q68
Type - Gráficos - Color de relleno de detalle bajo: 0
Type - Otros - Categoría: Muros; Nombre de familia: Muro básico
Type - Propiedades analíticas - Aspereza: 3; Absortancia: 0.7; Coeficiente de transferencia de calor (U): 187.5; Masa térmica: 17285.6; Resistencia térmica (R): 0.00533333
Cotas - Área: 0.36 m2; Longitud: 0.6 m; Volumen: 0.00288 m3
Estructura - Activar modelo analítico: no; Estructura: no; Uso estructural: No portante
Otros - Familia: Muro básico: VIVES PIGNETO HUMO 20x20; Familia y tipo: Muro básico: VIVES PIGNETO HUMO 20x20; ID de tipo: Muro básico: VIVES PIGNETO HUMO 20x20; Tipo: Muro básico: VIVES PIGNETO HUMO 20x20
Proceso por fases - Fase de creación: Nueva construcción
Restricciones - Delimitación de habitación: yes; Relacionado con masa: no; Desfase superior: 0 m; Distancia de extensión de base: 0 m; Distancia de extensión superior: 0 m; La base está enlazada: no; La parte superior está enlazada: no; Línea de ubicación: Cara de núcleo: Exterior; Restricción de base: Nivel: BENACO FLOOR TILES; Altura desconectada: 0.6 m; Desfase de base: -0.3 m
Pset_WallCommon - IsExternal: no; LoadBearing: no; ExtendToStructure: no; Reference: VIVES PIGNETO HUMO 20x20; ThermalTransmittance: 187.5 kg/K/s3
Pset_ManufacturerTypeInformation - Manufacturer: VIVES Azulejos y Gres S.A.

# IfcWallStandardCase: Muro básico:VIVES PIGNETO MAR 20x20, Muro básico:VIVES PIGNETO MAR 20x20:198226
In: BENACO FLOOR TILES
Type - PredefinedType: STANDARD; Material: VIVES PIGNETO MAR 20x20 0.008 m
Type - Construcción - Función: Interior; Envolvente en extremos: Ninguno; Envolvente en inserciones: Sin envolvente; Anchura: 0.008 m
Type - Datos - Model Name: PIGNETO MAR; Size: 20x20
Type - Datos de identidad - Fabricante: VIVES Azulejos y Gres S.A.; Modelo: PIGNETO MAR 20x20; Nombre de tipo: VIVES PIGNETO MAR 20x20; URL: http://www.vivesceramica.com/bim/r/4Q72
Type - Gráficos - Color de relleno de detalle bajo: 0
Type - Otros - Categoría: Muros; Nombre de familia: Muro básico
Type - Propiedades analíticas - Aspereza: 3; Absortancia: 0.7; Coeficiente de transferencia de calor (U): 187.5; Masa térmica: 17285.6; Resistencia térmica (R): 0.00533333
Cotas - Área: 0.36 m2; Longitud: 0.6 m; Volumen: 0.00288 m3
Estructura - Activar modelo analítico: no; Estructura: no; Uso estructural: No portante
Otros - Familia: Muro básico: VIVES PIGNETO MAR 20x20; Familia y tipo: Muro básico: VIVES PIGNETO MAR 20x20; ID de tipo: Muro básico: VIVES PIGNETO MAR 20x20; Tipo: Muro básico: VIVES PIGNETO MAR 20x20
Proceso por fases - Fase de creación: Nueva construcción
Restricciones - Delimitación de habitación: yes; Relacionado con masa: no; Desfase superior: 0 m; Distancia de extensión de base: 0 m; Distancia de extensión superior: 0 m; La base está enlazada: no; La parte superior está enlazada: no; Línea de ubicación: Cara de núcleo: Exterior; Restricción de base: Nivel: BENACO FLOOR TILES; Altura desconectada: 0.6 m; Desfase de base: -0.3 m
Pset_WallCommon - IsExternal: no; LoadBearing: no; ExtendToStructure: no; Reference: VIVES PIGNETO MAR 20x20; ThermalTransmittance: 187.5 kg/K/s3
Pset_ManufacturerTypeInformation - Manufacturer: VIVES Azulejos y Gres S.A.

# IfcWallStandardCase: Muro básico:VIVES PIGNETO NUBE 20x20, Muro básico:VIVES PIGNETO NUBE 20x20:198178
In: BENACO FLOOR TILES
Type - PredefinedType: STANDARD; Material: VIVES PIGNETO NUBE 20x20 0.008 m
Type - Construcción - Función: Interior; Envolvente en extremos: Ninguno; Envolvente en inserciones: Sin envolvente; Anchura: 0.008 m
Type - Datos - Model Name: PIGNETO NUBE; Size: 20x20
Type - Datos de identidad - Fabricante: VIVES Azulejos y Gres S.A.; Modelo: PIGNETO NUBE 20x20; Nombre de tipo: VIVES PIGNETO NUBE 20x20; URL: http://www.vivesceramica.com/bim/r/4Q69
Type - Gráficos - Color de relleno de detalle bajo: 0
Type - Otros - Categoría: Muros; Nombre de familia: Muro básico
Type - Propiedades analíticas - Aspereza: 3; Absortancia: 0.7; Coeficiente de transferencia de calor (U): 187.5; Masa térmica: 17285.6; Resistencia térmica (R): 0.00533333
Cotas - Área: 0.36 m2; Longitud: 0.6 m; Volumen: 0.00288 m3
Estructura - Activar modelo analítico: no; Estructura: no; Uso estructural: No portante
Otros - Familia: Muro básico: VIVES PIGNETO NUBE 20x20; Familia y tipo: Muro básico: VIVES PIGNETO NUBE 20x20; ID de tipo: Muro básico: VIVES PIGNETO NUBE 20x20; Tipo: Muro básico: VIVES PIGNETO NUBE 20x20
Proceso por fases - Fase de creación: Nueva construcción
Restricciones - Delimitación de habitación: yes; Relacionado con masa: no; Desfase superior: 0 m; Distancia de extensión de base: 0 m; Distancia de extensión superior: 0 m; La base está enlazada: no; La parte superior está enlazada: no; Línea de ubicación: Cara de núcleo: Exterior; Restricción de base: Nivel: BENACO FLOOR TILES; Altura desconectada: 0.6 m; Desfase de base: -0.3 m
Pset_WallCommon - IsExternal: no; LoadBearing: no; ExtendToStructure: no; Reference: VIVES PIGNETO NUBE 20x20; ThermalTransmittance: 187.5 kg/K/s3
Pset_ManufacturerTypeInformation - Manufacturer: VIVES Azulejos y Gres S.A.

# IfcWallStandardCase: Muro básico:VIVES TERCELLO BEIGE 20x20, Muro básico:VIVES TERCELLO BEIGE 20x20:198849
In: BENACO FLOOR TILES
Type - PredefinedType: STANDARD; Material: VIVES TERCELLO BEIGE 20x20 0.008 m
Type - Construcción - Función: Interior; Envolvente en extremos: Ninguno; Envolvente en inserciones: Sin envolvente; Anchura: 0.008 m
Type - Datos - Model Name: TERCELLO BEIGE; Size: 20x20
Type - Datos de identidad - Fabricante: VIVES Azulejos y Gres S.A.; Modelo: TERCELLO BEIGE 20x20; Nombre de tipo: VIVES TERCELLO BEIGE 20x20; URL: http://www.vivesceramica.com/bim/r/4Q75
Type - Gráficos - Color de relleno de detalle bajo: 0
Type - Otros - Categoría: Muros; Nombre de familia: Muro básico
Type - Propiedades analíticas - Aspereza: 3; Absortancia: 0.7; Coeficiente de transferencia de calor (U): 187.5; Masa térmica: 17285.6; Resistencia térmica (R): 0.00533333
Cotas - Área: 0.36 m2; Longitud: 0.6 m; Volumen: 0.00288 m3
Estructura - Activar modelo analítico: no; Estructura: no; Uso estructural: No portante
Otros - Familia: Muro básico: VIVES TERCELLO BEIGE 20x20; Familia y tipo: Muro básico: VIVES TERCELLO BEIGE 20x20; ID de tipo: Muro básico: VIVES TERCELLO BEIGE 20x20; Tipo: Muro básico: VIVES TERCELLO BEIGE 20x20
Proceso por fases - Fase de creación: Nueva construcción
Restricciones - Delimitación de habitación: yes; Relacionado con masa: no; Desfase superior: 0 m; Distancia de extensión de base: 0 m; Distancia de extensión superior: 0 m; La base está enlazada: no; La parte superior está enlazada: no; Línea de ubicación: Cara de núcleo: Exterior; Restricción de base: Nivel: BENACO FLOOR TILES; Altura desconectada: 0.6 m; Desfase de base: -1.3 m
Pset_WallCommon - IsExternal: no; LoadBearing: no; ExtendToStructure: no; Reference: VIVES TERCELLO BEIGE 20x20; ThermalTransmittance: 187.5 kg/K/s3
Pset_ManufacturerTypeInformation - Manufacturer: VIVES Azulejos y Gres S.A.

# IfcWallStandardCase: Muro básico:VIVES TERCELLO CORAL 20x20, Muro básico:VIVES TERCELLO CORAL 20x20:198865
In: BENACO FLOOR TILES
Type - PredefinedType: STANDARD; Material: VIVES TERCELLO CORAL 20x20 0.008 m
Type - Construcción - Función: Interior; Envolvente en extremos: Ninguno; Envolvente en inserciones: Sin envolvente; Anchura: 0.008 m
Type - Datos - Model Name: TERCELLO CORAL; Size: 20x20
Type - Datos de identidad - Fabricante: VIVES Azulejos y Gres S.A.; Modelo: TERCELLO CORAL 20x20; Nombre de tipo: VIVES TERCELLO CORAL 20x20; URL: http://www.vivesceramica.com/bim/r/4Q76
Type - Gráficos - Color de relleno de detalle bajo: 0
Type - Otros - Categoría: Muros; Nombre de familia: Muro básico
Type - Propiedades analíticas - Aspereza: 3; Absortancia: 0.7; Coeficiente de transferencia de calor (U): 187.5; Masa térmica: 17285.6; Resistencia térmica (R): 0.00533333
Cotas - Área: 0.36 m2; Longitud: 0.6 m; Volumen: 0.00288 m3
Estructura - Activar modelo analítico: no; Estructura: no; Uso estructural: No portante
Otros - Familia: Muro básico: VIVES TERCELLO CORAL 20x20; Familia y tipo: Muro básico: VIVES TERCELLO CORAL 20x20; ID de tipo: Muro básico: VIVES TERCELLO CORAL 20x20; Tipo: Muro básico: VIVES TERCELLO CORAL 20x20
Proceso por fases - Fase de creación: Nueva construcción
Restricciones - Delimitación de habitación: yes; Relacionado con masa: no; Desfase superior: 0 m; Distancia de extensión de base: 0 m; Distancia de extensión superior: 0 m; La base está enlazada: no; La parte superior está enlazada: no; Línea de ubicación: Cara de núcleo: Exterior; Restricción de base: Nivel: BENACO FLOOR TILES; Altura desconectada: 0.6 m; Desfase de base: -1.3 m
Pset_WallCommon - IsExternal: no; LoadBearing: no; ExtendToStructure: no; Reference: VIVES TERCELLO CORAL 20x20; ThermalTransmittance: 187.5 kg/K/s3
Pset_ManufacturerTypeInformation - Manufacturer: VIVES Azulejos y Gres S.A.

# IfcWallStandardCase: Muro básico:VIVES TERCELLO HUMO 20x20, Muro básico:VIVES TERCELLO HUMO 20x20:198817
In: BENACO FLOOR TILES
Type - PredefinedType: STANDARD; Material: VIVES TERCELLO HUMO 20x20 0.008 m
Type - Construcción - Función: Interior; Envolvente en extremos: Ninguno; Envolvente en inserciones: Sin envolvente; Anchura: 0.008 m
Type - Datos - Model Name: TERCELLO HUMO; Size: 20x20
Type - Datos de identidad - Fabricante: VIVES Azulejos y Gres S.A.; Modelo: PIGNETO TERCELLO 20x20; Nombre de tipo: VIVES TERCELLO HUMO 20x20; URL: http://www.vivesceramica.com/bim/r/4Q73
Type - Gráficos - Color de relleno de detalle bajo: 0
Type - Otros - Categoría: Muros; Nombre de familia: Muro básico
Type - Propiedades analíticas - Aspereza: 3; Absortancia: 0.7; Coeficiente de transferencia de calor (U): 187.5; Masa térmica: 17285.6; Resistencia térmica (R): 0.00533333
Cotas - Área: 0.36 m2; Longitud: 0.6 m; Volumen: 0.00288 m3
Estructura - Activar modelo analítico: no; Estructura: no; Uso estructural: No portante
Otros - Familia: Muro básico: VIVES TERCELLO HUMO 20x20; Familia y tipo: Muro básico: VIVES TERCELLO HUMO 20x20; ID de tipo: Muro básico: VIVES TERCELLO HUMO 20x20; Tipo: Muro básico: VIVES TERCELLO HUMO 20x20
Proceso por fases - Fase de creación: Nueva construcción
Restricciones - Delimitación de habitación: yes; Relacionado con masa: no; Desfase superior: 0 m; Distancia de extensión de base: 0 m; Distancia de extensión superior: 0 m; La base está enlazada: no; La parte superior está enlazada: no; Línea de ubicación: Cara de núcleo: Exterior; Restricción de base: Nivel: BENACO FLOOR TILES; Altura desconectada: 0.6 m; Desfase de base: -1.3 m
Pset_WallCommon - IsExternal: no; LoadBearing: no; ExtendToStructure: no; Reference: VIVES TERCELLO HUMO 20x20; ThermalTransmittance: 187.5 kg/K/s3
Pset_ManufacturerTypeInformation - Manufacturer: VIVES Azulejos y Gres S.A.

# IfcWallStandardCase: Muro básico:VIVES TERCELLO MAR 20x20, Muro básico:VIVES TERCELLO MAR 20x20:198881
In: BENACO FLOOR TILES
Type - PredefinedType: STANDARD; Material: VIVES TERCELLO MAR 20x20 0.008 m
Type - Construcción - Función: Interior; Envolvente en extremos: Ninguno; Envolvente en inserciones: Sin envolvente; Anchura: 0.008 m
Type - Datos - Model Name: TERCELLO MAR; Size: 20x20
Type - Datos de identidad - Fabricante: VIVES Azulejos y Gres S.A.; Modelo: TERCELLO MAR 20x20; Nombre de tipo: VIVES TERCELLO MAR 20x20; URL: http://www.vivesceramica.com/bim/r/4Q77
Type - Gráficos - Color de relleno de detalle bajo: 0
Type - Otros - Categoría: Muros; Nombre de familia: Muro básico
Type - Propiedades analíticas - Aspereza: 3; Absortancia: 0.7; Coeficiente de transferencia de calor (U): 187.5; Masa térmica: 17285.6; Resistencia térmica (R): 0.00533333
Cotas - Área: 0.36 m2; Longitud: 0.6 m; Volumen: 0.00288 m3
Estructura - Activar modelo analítico: no; Estructura: no; Uso estructural: No portante
Otros - Familia: Muro básico: VIVES TERCELLO MAR 20x20; Familia y tipo: Muro básico: VIVES TERCELLO MAR 20x20; ID de tipo: Muro básico: VIVES TERCELLO MAR 20x20; Tipo: Muro básico: VIVES TERCELLO MAR 20x20
Proceso por fases - Fase de creación: Nueva construcción
Restricciones - Delimitación de habitación: yes; Relacionado con masa: no; Desfase superior: 0 m; Distancia de extensión de base: 0 m; Distancia de extensión superior: 0 m; La base está enlazada: no; La parte superior está enlazada: no; Línea de ubicación: Cara de núcleo: Exterior; Restricción de base: Nivel: BENACO FLOOR TILES; Altura desconectada: 0.6 m; Desfase de base: -1.3 m
Pset_WallCommon - IsExternal: no; LoadBearing: no; ExtendToStructure: no; Reference: VIVES TERCELLO MAR 20x20; ThermalTransmittance: 187.5 kg/K/s3
Pset_ManufacturerTypeInformation - Manufacturer: VIVES Azulejos y Gres S.A.

# IfcWallStandardCase: Muro básico:VIVES TERCELLO NUBE 20x20, Muro básico:VIVES TERCELLO NUBE 20x20:198833
In: BENACO FLOOR TILES
Type - PredefinedType: STANDARD; Material: VIVES TERCELLO NUBE 20x20 0.008 m
Type - Construcción - Función: Interior; Envolvente en extremos: Ninguno; Envolvente en inserciones: Sin envolvente; Anchura: 0.008 m
Type - Datos - Model Name: TERCELLO NUBE; Size: 20x20
Type - Datos de identidad - Fabricante: VIVES Azulejos y Gres S.A.; Modelo: TERCELLO NUBE 20x20; Nombre de tipo: VIVES TERCELLO NUBE 20x20; URL: http://www.vivesceramica.com/bim/r/4Q74
Type - Gráficos - Color de relleno de detalle bajo: 0
Type - Otros - Categoría: Muros; Nombre de familia: Muro básico
Type - Propiedades analíticas - Aspereza: 3; Absortancia: 0.7; Coeficiente de transferencia de calor (U): 187.5; Masa térmica: 17285.6; Resistencia térmica (R): 0.00533333
Cotas - Área: 0.36 m2; Longitud: 0.6 m; Volumen: 0.00288 m3
Estructura - Activar modelo analítico: no; Estructura: no; Uso estructural: No portante
Otros - Familia: Muro básico: VIVES TERCELLO NUBE 20x20; Familia y tipo: Muro básico: VIVES TERCELLO NUBE 20x20; ID de tipo: Muro básico: VIVES TERCELLO NUBE 20x20; Tipo: Muro básico: VIVES TERCELLO NUBE 20x20
Proceso por fases - Fase de creación: Nueva construcción
Restricciones - Delimitación de habitación: yes; Relacionado con masa: no; Desfase superior: 0 m; Distancia de extensión de base: 0 m; Distancia de extensión superior: 0 m; La base está enlazada: no; La parte superior está enlazada: no; Línea de ubicación: Cara de núcleo: Exterior; Restricción de base: Nivel: BENACO FLOOR TILES; Altura desconectada: 0.6 m; Desfase de base: -1.3 m
Pset_WallCommon - IsExternal: no; LoadBearing: no; ExtendToStructure: no; Reference: VIVES TERCELLO NUBE 20x20; ThermalTransmittance: 187.5 kg/K/s3
Pset_ManufacturerTypeInformation - Manufacturer: VIVES Azulejos y Gres S.A.

# IfcWallStandardCase: Muro básico:VIVES VODEVIL ANTRACITA 20x20, Muro básico:VIVES VODEVIL ANTRACITA 20x20:195998
In: BENACO FLOOR TILES
Type - PredefinedType: STANDARD; Material: VIVES VODEVIL ANTRACITA 20x20 0.008 m
Type - Construcción - Función: Interior; Envolvente en extremos: Ninguno; Envolvente en inserciones: Sin envolvente; Anchura: 0.008 m
Type - Datos - Model Name: VODEVIL ANTRACITA; Size: 20x20
Type - Datos de identidad - Fabricante: VIVES Azulejos y Gres S.A.; Modelo: VODEVIL ANTRACITA 20x20; Nombre de tipo: VIVES VODEVIL ANTRACITA 20x20; URL: http://www.vivesceramica.com/bim/r/4P12
Type - Gráficos - Color de relleno de detalle bajo: 0
Type - Otros - Categoría: Muros; Nombre de familia: Muro básico
Type - Propiedades analíticas - Aspereza: 3; Absortancia: 0.7; Coeficiente de transferencia de calor (U): 187.5; Masa térmica: 17285.6; Resistencia térmica (R): 0.00533333
Cotas - Área: 0.36 m2; Longitud: 0.6 m; Volumen: 0.00288 m3
Estructura - Activar modelo analítico: no; Estructura: no; Uso estructural: No portante
Otros - Familia: Muro básico: VIVES VODEVIL ANTRACITA 20x20; Familia y tipo: Muro básico: VIVES VODEVIL ANTRACITA 20x20; ID de tipo: Muro básico: VIVES VODEVIL ANTRACITA 20x20; Tipo: Muro básico: VIVES VODEVIL ANTRACITA 20x20
Proceso por fases - Fase de creación: Nueva construcción
Restricciones - Delimitación de habitación: yes; Relacionado con masa: no; Desfase superior: 0 m; Distancia de extensión de base: 0 m; Distancia de extensión superior: 0 m; La base está enlazada: no; La parte superior está enlazada: no; Línea de ubicación: Cara de núcleo: Exterior; Restricción de base: Nivel: BENACO FLOOR TILES; Altura desconectada: 0.6 m; Desfase de base: 3.7 m
Pset_WallCommon - IsExternal: no; LoadBearing: no; ExtendToStructure: no; Reference: VIVES VODEVIL ANTRACITA 20x20; ThermalTransmittance: 187.5 kg/K/s3
Pset_ManufacturerTypeInformation - Manufacturer: VIVES Azulejos y Gres S.A.

# IfcWallStandardCase: Muro básico:VIVES VODEVIL BEIGE 20x20, Muro básico:VIVES VODEVIL BEIGE 20x20:196118
In: BENACO FLOOR TILES
Type - PredefinedType: STANDARD; Material: VIVES VODEVIL BEIGE 20x20 0.008 m
Type - Construcción - Función: Interior; Envolvente en extremos: Ninguno; Envolvente en inserciones: Sin envolvente; Anchura: 0.008 m
Type - Datos - Model Name: VODEVIL BEIGE; Size: 20x20
Type - Datos de identidad - Fabricante: VIVES Azulejos y Gres S.A.; Modelo: VODEVIL BEIGE 20x20; Nombre de tipo: VIVES VODEVIL BEIGE 20x20; URL: http://www.vivesceramica.com/bim/r/4P13
Type - Gráficos - Color de relleno de detalle bajo: 0
Type - Otros - Categoría: Muros; Nombre de familia: Muro básico
Type - Propiedades analíticas - Aspereza: 3; Absortancia: 0.7; Coeficiente de transferencia de calor (U): 187.5; Masa térmica: 17285.6; Resistencia térmica (R): 0.00533333
Cotas - Área: 0.36 m2; Longitud: 0.6 m; Volumen: 0.00288 m3
Estructura - Activar modelo analítico: no; Estructura: no; Uso estructural: No portante
Otros - Familia: Muro básico: VIVES VODEVIL BEIGE 20x20; Familia y tipo: Muro básico: VIVES VODEVIL BEIGE 20x20; ID de tipo: Muro básico: VIVES VODEVIL BEIGE 20x20; Tipo: Muro básico: VIVES VODEVIL BEIGE 20x20
Proceso por fases - Fase de creación: Nueva construcción
Restricciones - Delimitación de habitación: yes; Relacionado con masa: no; Desfase superior: 0 m; Distancia de extensión de base: 0 m; Distancia de extensión superior: 0 m; La base está enlazada: no; La parte superior está enlazada: no; Línea de ubicación: Cara de núcleo: Exterior; Restricción de base: Nivel: BENACO FLOOR TILES; Altura desconectada: 0.6 m; Desfase de base: 2.7 m
Pset_WallCommon - IsExternal: no; LoadBearing: no; ExtendToStructure: no; Reference: VIVES VODEVIL BEIGE 20x20; ThermalTransmittance: 187.5 kg/K/s3
Pset_ManufacturerTypeInformation - Manufacturer: VIVES Azulejos y Gres S.A.

# IfcWallStandardCase: Muro básico:VIVES VODEVIL CORAL 20x20, Muro básico:VIVES VODEVIL CORAL 20x20:196157
In: BENACO FLOOR TILES
Type - PredefinedType: STANDARD; Material: VIVES VODEVIL CORAL 20x20 0.008 m
Type - Construcción - Función: Interior; Envolvente en extremos: Ninguno; Envolvente en inserciones: Sin envolvente; Anchura: 0.008 m
Type - Datos - Model Name: VODEVIL CORAL; Size: 20x20
Type - Datos de identidad - Fabricante: VIVES Azulejos y Gres S.A.; Modelo: VODEVIL CORAL 20x20; Nombre de tipo: VIVES VODEVIL CORAL 20x20; URL: http://www.vivesceramica.com/bim/r/4Q78
Type - Gráficos - Color de relleno de detalle bajo: 0
Type - Otros - Categoría: Muros; Nombre de familia: Muro básico
Type - Propiedades analíticas - Aspereza: 3; Absortancia: 0.7; Coeficiente de transferencia de calor (U): 187.5; Masa térmica: 17285.6; Resistencia térmica (R): 0.00533333
Cotas - Área: 0.36 m2; Longitud: 0.6 m; Volumen: 0.00288 m3
Estructura - Activar modelo analítico: no; Estructura: no; Uso estructural: No portante
Otros - Familia: Muro básico: VIVES VODEVIL CORAL 20x20; Familia y tipo: Muro básico: VIVES VODEVIL CORAL 20x20; ID de tipo: Muro básico: VIVES VODEVIL CORAL 20x20; Tipo: Muro básico: VIVES VODEVIL CORAL 20x20
Proceso por fases - Fase de creación: Nueva construcción
Restricciones - Delimitación de habitación: yes; Relacionado con masa: no; Desfase superior: 0 m; Distancia de extensión de base: 0 m; Distancia de extensión superior: 0 m; La base está enlazada: no; La parte superior está enlazada: no; Línea de ubicación: Cara de núcleo: Exterior; Restricción de base: Nivel: BENACO FLOOR TILES; Altura desconectada: 0.6 m; Desfase de base: 2.7 m
Pset_WallCommon - IsExternal: no; LoadBearing: no; ExtendToStructure: no; Reference: VIVES VODEVIL CORAL 20x20; ThermalTransmittance: 187.5 kg/K/s3
Pset_ManufacturerTypeInformation - Manufacturer: VIVES Azulejos y Gres S.A.

# IfcWallStandardCase: Muro básico:VIVES VODEVIL HUMO 20x20, Muro básico:VIVES VODEVIL HUMO 20x20:196086
In: BENACO FLOOR TILES
Type - PredefinedType: STANDARD; Material: VIVES VODEVIL HUMO 20x20 0.008 m
Type - Construcción - Función: Interior; Envolvente en extremos: Ninguno; Envolvente en inserciones: Sin envolvente; Anchura: 0.008 m
Type - Datos - Model Name: VODEVIL HUMO; Size: 20x20
Type - Datos de identidad - Fabricante: VIVES Azulejos y Gres S.A.; Modelo: VODEVIL HUMO 20x20; Nombre de tipo: VIVES VODEVIL HUMO 20x20; URL: http://www.vivesceramica.com/bim/r/4P14
Type - Gráficos - Color de relleno de detalle bajo: 0
Type - Otros - Categoría: Muros; Nombre de familia: Muro básico
Type - Propiedades analíticas - Aspereza: 3; Absortancia: 0.7; Coeficiente de transferencia de calor (U): 187.5; Masa térmica: 17285.6; Resistencia térmica (R): 0.00533333
Cotas - Área: 0.36 m2; Longitud: 0.6 m; Volumen: 0.00288 m3
Estructura - Activar modelo analítico: no; Estructura: no; Uso estructural: No portante
Otros - Familia: Muro básico: VIVES VODEVIL HUMO 20x20; Familia y tipo: Muro básico: VIVES VODEVIL HUMO 20x20; ID de tipo: Muro básico: VIVES VODEVIL HUMO 20x20; Tipo: Muro básico: VIVES VODEVIL HUMO 20x20
Proceso por fases - Fase de creación: Nueva construcción
Restricciones - Delimitación de habitación: yes; Relacionado con masa: no; Desfase superior: 0 m; Distancia de extensión de base: 0 m; Distancia de extensión superior: 0 m; La base está enlazada: no; La parte superior está enlazada: no; Línea de ubicación: Cara de núcleo: Exterior; Restricción de base: Nivel: BENACO FLOOR TILES; Altura desconectada: 0.6 m; Desfase de base: 2.7 m
Pset_WallCommon - IsExternal: no; LoadBearing: no; ExtendToStructure: no; Reference: VIVES VODEVIL HUMO 20x20; ThermalTransmittance: 187.5 kg/K/s3
Pset_ManufacturerTypeInformation - Manufacturer: VIVES Azulejos y Gres S.A.

# IfcWallStandardCase: Muro básico:VIVES VODEVIL MAR 20x20, Muro básico:VIVES VODEVIL MAR 20x20:196189
In: BENACO FLOOR TILES
Type - PredefinedType: STANDARD; Material: VIVES VODEVIL MAR 20x20 0.008 m
Type - Construcción - Función: Interior; Envolvente en extremos: Ninguno; Envolvente en inserciones: Sin envolvente; Anchura: 0.008 m
Type - Datos - Model Name: VODEVIL MAR; Size: 20x20
Type - Datos de identidad - Fabricante: VIVES Azulejos y Gres S.A.; Modelo: VODEVIL MAR 20x20; Nombre de tipo: VIVES VODEVIL MAR 20x20; URL: http://www.vivesceramica.com/bim/r/4Q79
Type - Gráficos - Color de relleno de detalle bajo: 0
Type - Otros - Categoría: Muros; Nombre de familia: Muro básico
Type - Propiedades analíticas - Aspereza: 3; Absortancia: 0.7; Coeficiente de transferencia de calor (U): 187.5; Masa térmica: 17285.6; Resistencia térmica (R): 0.00533333
Cotas - Área: 0.36 m2; Longitud: 0.6 m; Volumen: 0.00288 m3
Estructura - Activar modelo analítico: no; Estructura: no; Uso estructural: No portante
Otros - Familia: Muro básico: VIVES VODEVIL MAR 20x20; Familia y tipo: Muro básico: VIVES VODEVIL MAR 20x20; ID de tipo: Muro básico: VIVES VODEVIL MAR 20x20; Tipo: Muro básico: VIVES VODEVIL MAR 20x20
Proceso por fases - Fase de creación: Nueva construcción
Restricciones - Delimitación de habitación: yes; Relacionado con masa: no; Desfase superior: 0 m; Distancia de extensión de base: 0 m; Distancia de extensión superior: 0 m; La base está enlazada: no; La parte superior está enlazada: no; Línea de ubicación: Cara de núcleo: Exterior; Restricción de base: Nivel: BENACO FLOOR TILES; Altura desconectada: 0.6 m; Desfase de base: 2.7 m
Pset_WallCommon - IsExternal: no; LoadBearing: no; ExtendToStructure: no; Reference: VIVES VODEVIL MAR 20x20; ThermalTransmittance: 187.5 kg/K/s3
Pset_ManufacturerTypeInformation - Manufacturer: VIVES Azulejos y Gres S.A.

# IfcWallStandardCase: Muro básico:VIVES VODEVIL MARRÓN 20x20, Muro básico:VIVES VODEVIL MARRÓN 20x20:196054
In: BENACO FLOOR TILES
Type - PredefinedType: STANDARD; Material: VIVES VODEVIL MARRON 20x20 0.008 m
Type - Construcción - Función: Interior; Envolvente en extremos: Ninguno; Envolvente en inserciones: Sin envolvente; Anchura: 0.008 m
Type - Datos - Model Name: VODEVIL MARRÓN; Size: 20x20
Type - Datos de identidad - Fabricante: VIVES Azulejos y Gres S.A.; Modelo: VODEVIL MARRÓN 20x20; Nombre de tipo: VIVES VODEVIL MARRÓN 20x20; URL: http://www.vivesceramica.com/bim/r/4P15
Type - Gráficos - Color de relleno de detalle bajo: 0
Type - Otros - Categoría: Muros; Nombre de familia: Muro básico
Type - Propiedades analíticas - Aspereza: 3; Absortancia: 0.7; Coeficiente de transferencia de calor (U): 187.5; Masa térmica: 17285.6; Resistencia térmica (R): 0.00533333
Cotas - Área: 0.36 m2; Longitud: 0.6 m; Volumen: 0.00288 m3
Estructura - Activar modelo analítico: no; Estructura: no; Uso estructural: No portante
Otros - Familia: Muro básico: VIVES VODEVIL MARRÓN 20x20; Familia y tipo: Muro básico: VIVES VODEVIL MARRÓN 20x20; ID de tipo: Muro básico: VIVES VODEVIL MARRÓN 20x20; Tipo: Muro básico: VIVES VODEVIL MARRÓN 20x20
Proceso por fases - Fase de creación: Nueva construcción
Restricciones - Delimitación de habitación: yes; Relacionado con masa: no; Desfase superior: 0 m; Distancia de extensión de base: 0 m; Distancia de extensión superior: 0 m; La base está enlazada: no; La parte superior está enlazada: no; Línea de ubicación: Cara de núcleo: Exterior; Restricción de base: Nivel: BENACO FLOOR TILES; Altura desconectada: 0.6 m; Desfase de base: 3.7 m
Pset_WallCommon - IsExternal: no; LoadBearing: no; ExtendToStructure: no; Reference: VIVES VODEVIL MARRÓN 20x20; ThermalTransmittance: 187.5 kg/K/s3
Pset_ManufacturerTypeInformation - Manufacturer: VIVES Azulejos y Gres S.A.

# IfcWallStandardCase: Muro básico:VIVES VODEVIL NACAR 20x20, Muro básico:VIVES VODEVIL NACAR 20x20:190692
In: BENACO FLOOR TILES
Type - PredefinedType: STANDARD; Material: VIVES VODEVIL NACAR 20x20 0.008 m
Type - Construcción - Función: Interior; Anchura: 0.008 m; Envolvente en extremos: Ninguno; Envolvente en inserciones: Sin envolvente
Type - Datos - Model Name: VODEVIL NACAR; Size: 20x20
Type - Datos de identidad - Fabricante: VIVES Azulejos y Gres S.A.; Modelo: VODEVIL NACAR 20x20; Nombre de tipo: VIVES VODEVIL NACAR 20x20; URL: http://www.vivesceramica.com/bim/r/4P16
Type - Gráficos - Color de relleno de detalle bajo: 0
Type - Otros - Categoría: Muros; Nombre de familia: Muro básico
Type - Propiedades analíticas - Aspereza: 3; Absortancia: 0.7; Coeficiente de transferencia de calor (U): 187.5; Masa térmica: 17285.6; Resistencia térmica (R): 0.00533333
Cotas - Área: 0.36 m2; Longitud: 0.6 m; Volumen: 0.00288 m3
Estructura - Activar modelo analítico: no; Estructura: no; Uso estructural: No portante
Otros - Familia: Muro básico: VIVES VODEVIL NACAR 20x20; Familia y tipo: Muro básico: VIVES VODEVIL NACAR 20x20; ID de tipo: Muro básico: VIVES VODEVIL NACAR 20x20; Tipo: Muro básico: VIVES VODEVIL NACAR 20x20
Proceso por fases - Fase de creación: Nueva construcción
Restricciones - Delimitación de habitación: yes; Relacionado con masa: no; Altura desconectada: 0.6 m; Desfase de base: 3.7 m; Desfase superior: 0 m; Distancia de extensión de base: 0 m; Distancia de extensión superior: 0 m; La base está enlazada: no; La parte superior está enlazada: no; Línea de ubicación: Cara de núcleo: Exterior; Restricción de base: Nivel: BENACO FLOOR TILES
Pset_WallCommon - Reference: VIVES VODEVIL NACAR 20x20; IsExternal: no; LoadBearing: no; ExtendToStructure: no; ThermalTransmittance: 187.5 kg/K/s3
Pset_ManufacturerTypeInformation - Manufacturer: VIVES Azulejos y Gres S.A.

# IfcWallStandardCase: Muro básico:VIVES VODEVIL NUBE 20x20, Muro básico:VIVES VODEVIL NUBE 20x20:196102
In: BENACO FLOOR TILES
Type - PredefinedType: STANDARD; Material: VIVES VODEVIL NUBE 20x20 0.008 m
Type - Construcción - Función: Interior; Envolvente en extremos: Ninguno; Envolvente en inserciones: Sin envolvente; Anchura: 0.008 m
Type - Datos - Model Name: VODEVIL NUBE; Size: 20x20
Type - Datos de identidad - Fabricante: VIVES Azulejos y Gres S.A.; Modelo: VODEVIL NUBE 20x20; Nombre de tipo: VIVES VODEVIL NUBE 20x20; URL: http://www.vivesceramica.com/bim/r/4P17
Type - Gráficos - Color de relleno de detalle bajo: 0
Type - Otros - Categoría: Muros; Nombre de familia: Muro básico
Type - Propiedades analíticas - Aspereza: 3; Absortancia: 0.7; Coeficiente de transferencia de calor (U): 187.5; Masa térmica: 17285.6; Resistencia térmica (R): 0.00533333
Cotas - Área: 0.36 m2; Longitud: 0.6 m; Volumen: 0.00288 m3
Estructura - Activar modelo analítico: no; Estructura: no; Uso estructural: No portante
Otros - Familia: Muro básico: VIVES VODEVIL NUBE 20x20; Familia y tipo: Muro básico: VIVES VODEVIL NUBE 20x20; ID de tipo: Muro básico: VIVES VODEVIL NUBE 20x20; Tipo: Muro básico: VIVES VODEVIL NUBE 20x20
Proceso por fases - Fase de creación: Nueva construcción
Restricciones - Delimitación de habitación: yes; Relacionado con masa: no; Desfase superior: 0 m; Distancia de extensión de base: 0 m; Distancia de extensión superior: 0 m; La base está enlazada: no; La parte superior está enlazada: no; Línea de ubicación: Cara de núcleo: Exterior; Restricción de base: Nivel: BENACO FLOOR TILES; Altura desconectada: 0.6 m; Desfase de base: 2.7 m
Pset_WallCommon - IsExternal: no; LoadBearing: no; ExtendToStructure: no; Reference: VIVES VODEVIL NUBE 20x20; ThermalTransmittance: 187.5 kg/K/s3
Pset_ManufacturerTypeInformation - Manufacturer: VIVES Azulejos y Gres S.A.
